# Generated by FakeRAM 2.0
VERSION 5.7 ;
BUSBITCHARS "[]" ;
PROPERTYDEFINITIONS
  MACRO width INTEGER ;
  MACRO depth INTEGER ;
  MACRO banks INTEGER ;
END PROPERTYDEFINITIONS
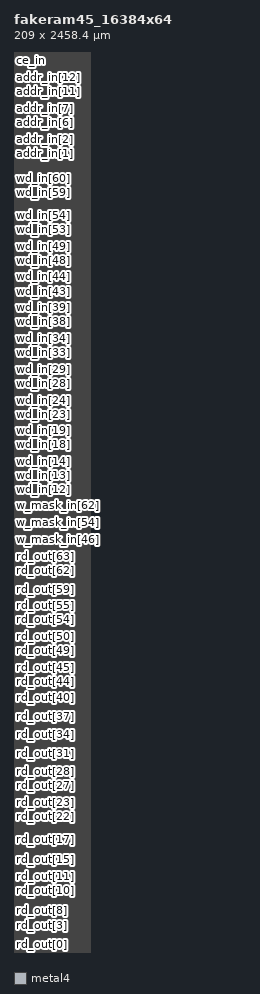
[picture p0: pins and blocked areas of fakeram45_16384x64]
MACRO fakeram45_16384x64
  PROPERTY width 64 ;
  PROPERTY depth 16384 ;
  PROPERTY banks 4 ;
  FOREIGN fakeram45_16384x64 0 0 ;
  SYMMETRY X Y R90 ;
  SIZE 209.000 BY 2458.400 ;
  CLASS BLOCK ;
  PIN rd_out[0]
    DIRECTION OUTPUT ;
    USE SIGNAL ;
    SHAPE ABUTMENT ;
    PORT
      LAYER metal4 ;
      RECT 0.000 0.280 0.140 0.420 ;
    END
  END rd_out[0]
  PIN rd_out[1]
    DIRECTION OUTPUT ;
    USE SIGNAL ;
    SHAPE ABUTMENT ;
    PORT
      LAYER metal4 ;
      RECT 0.000 17.080 0.140 17.220 ;
    END
  END rd_out[1]
  PIN rd_out[2]
    DIRECTION OUTPUT ;
    USE SIGNAL ;
    SHAPE ABUTMENT ;
    PORT
      LAYER metal4 ;
      RECT 0.000 33.880 0.140 34.020 ;
    END
  END rd_out[2]
  PIN rd_out[3]
    DIRECTION OUTPUT ;
    USE SIGNAL ;
    SHAPE ABUTMENT ;
    PORT
      LAYER metal4 ;
      RECT 0.000 50.680 0.140 50.820 ;
    END
  END rd_out[3]
  PIN rd_out[4]
    DIRECTION OUTPUT ;
    USE SIGNAL ;
    SHAPE ABUTMENT ;
    PORT
      LAYER metal4 ;
      RECT 0.000 67.480 0.140 67.620 ;
    END
  END rd_out[4]
  PIN rd_out[5]
    DIRECTION OUTPUT ;
    USE SIGNAL ;
    SHAPE ABUTMENT ;
    PORT
      LAYER metal4 ;
      RECT 0.000 84.280 0.140 84.420 ;
    END
  END rd_out[5]
  PIN rd_out[6]
    DIRECTION OUTPUT ;
    USE SIGNAL ;
    SHAPE ABUTMENT ;
    PORT
      LAYER metal4 ;
      RECT 0.000 101.080 0.140 101.220 ;
    END
  END rd_out[6]
  PIN rd_out[7]
    DIRECTION OUTPUT ;
    USE SIGNAL ;
    SHAPE ABUTMENT ;
    PORT
      LAYER metal4 ;
      RECT 0.000 117.880 0.140 118.020 ;
    END
  END rd_out[7]
  PIN rd_out[8]
    DIRECTION OUTPUT ;
    USE SIGNAL ;
    SHAPE ABUTMENT ;
    PORT
      LAYER metal4 ;
      RECT 0.000 134.680 0.140 134.820 ;
    END
  END rd_out[8]
  PIN rd_out[9]
    DIRECTION OUTPUT ;
    USE SIGNAL ;
    SHAPE ABUTMENT ;
    PORT
      LAYER metal4 ;
      RECT 0.000 151.480 0.140 151.620 ;
    END
  END rd_out[9]
  PIN rd_out[10]
    DIRECTION OUTPUT ;
    USE SIGNAL ;
    SHAPE ABUTMENT ;
    PORT
      LAYER metal4 ;
      RECT 0.000 168.280 0.140 168.420 ;
    END
  END rd_out[10]
  PIN rd_out[11]
    DIRECTION OUTPUT ;
    USE SIGNAL ;
    SHAPE ABUTMENT ;
    PORT
      LAYER metal4 ;
      RECT 0.000 185.080 0.140 185.220 ;
    END
  END rd_out[11]
  PIN rd_out[12]
    DIRECTION OUTPUT ;
    USE SIGNAL ;
    SHAPE ABUTMENT ;
    PORT
      LAYER metal4 ;
      RECT 0.000 201.880 0.140 202.020 ;
    END
  END rd_out[12]
  PIN rd_out[13]
    DIRECTION OUTPUT ;
    USE SIGNAL ;
    SHAPE ABUTMENT ;
    PORT
      LAYER metal4 ;
      RECT 0.000 218.680 0.140 218.820 ;
    END
  END rd_out[13]
  PIN rd_out[14]
    DIRECTION OUTPUT ;
    USE SIGNAL ;
    SHAPE ABUTMENT ;
    PORT
      LAYER metal4 ;
      RECT 0.000 235.480 0.140 235.620 ;
    END
  END rd_out[14]
  PIN rd_out[15]
    DIRECTION OUTPUT ;
    USE SIGNAL ;
    SHAPE ABUTMENT ;
    PORT
      LAYER metal4 ;
      RECT 0.000 252.280 0.140 252.420 ;
    END
  END rd_out[15]
  PIN rd_out[16]
    DIRECTION OUTPUT ;
    USE SIGNAL ;
    SHAPE ABUTMENT ;
    PORT
      LAYER metal4 ;
      RECT 0.000 269.080 0.140 269.220 ;
    END
  END rd_out[16]
  PIN rd_out[17]
    DIRECTION OUTPUT ;
    USE SIGNAL ;
    SHAPE ABUTMENT ;
    PORT
      LAYER metal4 ;
      RECT 0.000 285.880 0.140 286.020 ;
    END
  END rd_out[17]
  PIN rd_out[18]
    DIRECTION OUTPUT ;
    USE SIGNAL ;
    SHAPE ABUTMENT ;
    PORT
      LAYER metal4 ;
      RECT 0.000 302.680 0.140 302.820 ;
    END
  END rd_out[18]
  PIN rd_out[19]
    DIRECTION OUTPUT ;
    USE SIGNAL ;
    SHAPE ABUTMENT ;
    PORT
      LAYER metal4 ;
      RECT 0.000 319.480 0.140 319.620 ;
    END
  END rd_out[19]
  PIN rd_out[20]
    DIRECTION OUTPUT ;
    USE SIGNAL ;
    SHAPE ABUTMENT ;
    PORT
      LAYER metal4 ;
      RECT 0.000 336.280 0.140 336.420 ;
    END
  END rd_out[20]
  PIN rd_out[21]
    DIRECTION OUTPUT ;
    USE SIGNAL ;
    SHAPE ABUTMENT ;
    PORT
      LAYER metal4 ;
      RECT 0.000 353.080 0.140 353.220 ;
    END
  END rd_out[21]
  PIN rd_out[22]
    DIRECTION OUTPUT ;
    USE SIGNAL ;
    SHAPE ABUTMENT ;
    PORT
      LAYER metal4 ;
      RECT 0.000 369.880 0.140 370.020 ;
    END
  END rd_out[22]
  PIN rd_out[23]
    DIRECTION OUTPUT ;
    USE SIGNAL ;
    SHAPE ABUTMENT ;
    PORT
      LAYER metal4 ;
      RECT 0.000 386.680 0.140 386.820 ;
    END
  END rd_out[23]
  PIN rd_out[24]
    DIRECTION OUTPUT ;
    USE SIGNAL ;
    SHAPE ABUTMENT ;
    PORT
      LAYER metal4 ;
      RECT 0.000 403.480 0.140 403.620 ;
    END
  END rd_out[24]
  PIN rd_out[25]
    DIRECTION OUTPUT ;
    USE SIGNAL ;
    SHAPE ABUTMENT ;
    PORT
      LAYER metal4 ;
      RECT 0.000 420.280 0.140 420.420 ;
    END
  END rd_out[25]
  PIN rd_out[26]
    DIRECTION OUTPUT ;
    USE SIGNAL ;
    SHAPE ABUTMENT ;
    PORT
      LAYER metal4 ;
      RECT 0.000 437.080 0.140 437.220 ;
    END
  END rd_out[26]
  PIN rd_out[27]
    DIRECTION OUTPUT ;
    USE SIGNAL ;
    SHAPE ABUTMENT ;
    PORT
      LAYER metal4 ;
      RECT 0.000 453.880 0.140 454.020 ;
    END
  END rd_out[27]
  PIN rd_out[28]
    DIRECTION OUTPUT ;
    USE SIGNAL ;
    SHAPE ABUTMENT ;
    PORT
      LAYER metal4 ;
      RECT 0.000 470.680 0.140 470.820 ;
    END
  END rd_out[28]
  PIN rd_out[29]
    DIRECTION OUTPUT ;
    USE SIGNAL ;
    SHAPE ABUTMENT ;
    PORT
      LAYER metal4 ;
      RECT 0.000 487.480 0.140 487.620 ;
    END
  END rd_out[29]
  PIN rd_out[30]
    DIRECTION OUTPUT ;
    USE SIGNAL ;
    SHAPE ABUTMENT ;
    PORT
      LAYER metal4 ;
      RECT 0.000 504.280 0.140 504.420 ;
    END
  END rd_out[30]
  PIN rd_out[31]
    DIRECTION OUTPUT ;
    USE SIGNAL ;
    SHAPE ABUTMENT ;
    PORT
      LAYER metal4 ;
      RECT 0.000 521.080 0.140 521.220 ;
    END
  END rd_out[31]
  PIN rd_out[32]
    DIRECTION OUTPUT ;
    USE SIGNAL ;
    SHAPE ABUTMENT ;
    PORT
      LAYER metal4 ;
      RECT 0.000 537.880 0.140 538.020 ;
    END
  END rd_out[32]
  PIN rd_out[33]
    DIRECTION OUTPUT ;
    USE SIGNAL ;
    SHAPE ABUTMENT ;
    PORT
      LAYER metal4 ;
      RECT 0.000 554.680 0.140 554.820 ;
    END
  END rd_out[33]
  PIN rd_out[34]
    DIRECTION OUTPUT ;
    USE SIGNAL ;
    SHAPE ABUTMENT ;
    PORT
      LAYER metal4 ;
      RECT 0.000 571.480 0.140 571.620 ;
    END
  END rd_out[34]
  PIN rd_out[35]
    DIRECTION OUTPUT ;
    USE SIGNAL ;
    SHAPE ABUTMENT ;
    PORT
      LAYER metal4 ;
      RECT 0.000 588.280 0.140 588.420 ;
    END
  END rd_out[35]
  PIN rd_out[36]
    DIRECTION OUTPUT ;
    USE SIGNAL ;
    SHAPE ABUTMENT ;
    PORT
      LAYER metal4 ;
      RECT 0.000 605.080 0.140 605.220 ;
    END
  END rd_out[36]
  PIN rd_out[37]
    DIRECTION OUTPUT ;
    USE SIGNAL ;
    SHAPE ABUTMENT ;
    PORT
      LAYER metal4 ;
      RECT 0.000 621.880 0.140 622.020 ;
    END
  END rd_out[37]
  PIN rd_out[38]
    DIRECTION OUTPUT ;
    USE SIGNAL ;
    SHAPE ABUTMENT ;
    PORT
      LAYER metal4 ;
      RECT 0.000 638.680 0.140 638.820 ;
    END
  END rd_out[38]
  PIN rd_out[39]
    DIRECTION OUTPUT ;
    USE SIGNAL ;
    SHAPE ABUTMENT ;
    PORT
      LAYER metal4 ;
      RECT 0.000 655.480 0.140 655.620 ;
    END
  END rd_out[39]
  PIN rd_out[40]
    DIRECTION OUTPUT ;
    USE SIGNAL ;
    SHAPE ABUTMENT ;
    PORT
      LAYER metal4 ;
      RECT 0.000 672.280 0.140 672.420 ;
    END
  END rd_out[40]
  PIN rd_out[41]
    DIRECTION OUTPUT ;
    USE SIGNAL ;
    SHAPE ABUTMENT ;
    PORT
      LAYER metal4 ;
      RECT 0.000 689.080 0.140 689.220 ;
    END
  END rd_out[41]
  PIN rd_out[42]
    DIRECTION OUTPUT ;
    USE SIGNAL ;
    SHAPE ABUTMENT ;
    PORT
      LAYER metal4 ;
      RECT 0.000 705.880 0.140 706.020 ;
    END
  END rd_out[42]
  PIN rd_out[43]
    DIRECTION OUTPUT ;
    USE SIGNAL ;
    SHAPE ABUTMENT ;
    PORT
      LAYER metal4 ;
      RECT 0.000 722.680 0.140 722.820 ;
    END
  END rd_out[43]
  PIN rd_out[44]
    DIRECTION OUTPUT ;
    USE SIGNAL ;
    SHAPE ABUTMENT ;
    PORT
      LAYER metal4 ;
      RECT 0.000 739.480 0.140 739.620 ;
    END
  END rd_out[44]
  PIN rd_out[45]
    DIRECTION OUTPUT ;
    USE SIGNAL ;
    SHAPE ABUTMENT ;
    PORT
      LAYER metal4 ;
      RECT 0.000 756.280 0.140 756.420 ;
    END
  END rd_out[45]
  PIN rd_out[46]
    DIRECTION OUTPUT ;
    USE SIGNAL ;
    SHAPE ABUTMENT ;
    PORT
      LAYER metal4 ;
      RECT 0.000 773.080 0.140 773.220 ;
    END
  END rd_out[46]
  PIN rd_out[47]
    DIRECTION OUTPUT ;
    USE SIGNAL ;
    SHAPE ABUTMENT ;
    PORT
      LAYER metal4 ;
      RECT 0.000 789.880 0.140 790.020 ;
    END
  END rd_out[47]
  PIN rd_out[48]
    DIRECTION OUTPUT ;
    USE SIGNAL ;
    SHAPE ABUTMENT ;
    PORT
      LAYER metal4 ;
      RECT 0.000 806.680 0.140 806.820 ;
    END
  END rd_out[48]
  PIN rd_out[49]
    DIRECTION OUTPUT ;
    USE SIGNAL ;
    SHAPE ABUTMENT ;
    PORT
      LAYER metal4 ;
      RECT 0.000 823.480 0.140 823.620 ;
    END
  END rd_out[49]
  PIN rd_out[50]
    DIRECTION OUTPUT ;
    USE SIGNAL ;
    SHAPE ABUTMENT ;
    PORT
      LAYER metal4 ;
      RECT 0.000 840.280 0.140 840.420 ;
    END
  END rd_out[50]
  PIN rd_out[51]
    DIRECTION OUTPUT ;
    USE SIGNAL ;
    SHAPE ABUTMENT ;
    PORT
      LAYER metal4 ;
      RECT 0.000 857.080 0.140 857.220 ;
    END
  END rd_out[51]
  PIN rd_out[52]
    DIRECTION OUTPUT ;
    USE SIGNAL ;
    SHAPE ABUTMENT ;
    PORT
      LAYER metal4 ;
      RECT 0.000 873.880 0.140 874.020 ;
    END
  END rd_out[52]
  PIN rd_out[53]
    DIRECTION OUTPUT ;
    USE SIGNAL ;
    SHAPE ABUTMENT ;
    PORT
      LAYER metal4 ;
      RECT 0.000 890.680 0.140 890.820 ;
    END
  END rd_out[53]
  PIN rd_out[54]
    DIRECTION OUTPUT ;
    USE SIGNAL ;
    SHAPE ABUTMENT ;
    PORT
      LAYER metal4 ;
      RECT 0.000 907.480 0.140 907.620 ;
    END
  END rd_out[54]
  PIN rd_out[55]
    DIRECTION OUTPUT ;
    USE SIGNAL ;
    SHAPE ABUTMENT ;
    PORT
      LAYER metal4 ;
      RECT 0.000 924.280 0.140 924.420 ;
    END
  END rd_out[55]
  PIN rd_out[56]
    DIRECTION OUTPUT ;
    USE SIGNAL ;
    SHAPE ABUTMENT ;
    PORT
      LAYER metal4 ;
      RECT 0.000 941.080 0.140 941.220 ;
    END
  END rd_out[56]
  PIN rd_out[57]
    DIRECTION OUTPUT ;
    USE SIGNAL ;
    SHAPE ABUTMENT ;
    PORT
      LAYER metal4 ;
      RECT 0.000 957.880 0.140 958.020 ;
    END
  END rd_out[57]
  PIN rd_out[58]
    DIRECTION OUTPUT ;
    USE SIGNAL ;
    SHAPE ABUTMENT ;
    PORT
      LAYER metal4 ;
      RECT 0.000 974.680 0.140 974.820 ;
    END
  END rd_out[58]
  PIN rd_out[59]
    DIRECTION OUTPUT ;
    USE SIGNAL ;
    SHAPE ABUTMENT ;
    PORT
      LAYER metal4 ;
      RECT 0.000 991.480 0.140 991.620 ;
    END
  END rd_out[59]
  PIN rd_out[60]
    DIRECTION OUTPUT ;
    USE SIGNAL ;
    SHAPE ABUTMENT ;
    PORT
      LAYER metal4 ;
      RECT 0.000 1008.280 0.140 1008.420 ;
    END
  END rd_out[60]
  PIN rd_out[61]
    DIRECTION OUTPUT ;
    USE SIGNAL ;
    SHAPE ABUTMENT ;
    PORT
      LAYER metal4 ;
      RECT 0.000 1025.080 0.140 1025.220 ;
    END
  END rd_out[61]
  PIN rd_out[62]
    DIRECTION OUTPUT ;
    USE SIGNAL ;
    SHAPE ABUTMENT ;
    PORT
      LAYER metal4 ;
      RECT 0.000 1041.880 0.140 1042.020 ;
    END
  END rd_out[62]
  PIN rd_out[63]
    DIRECTION OUTPUT ;
    USE SIGNAL ;
    SHAPE ABUTMENT ;
    PORT
      LAYER metal4 ;
      RECT 0.000 1058.680 0.140 1058.820 ;
    END
  END rd_out[63]
  PIN wd_in[0]
    DIRECTION INPUT ;
    USE SIGNAL ;
    SHAPE ABUTMENT ;
    PORT
      LAYER metal4 ;
      RECT 0.000 1082.760 0.140 1082.900 ;
    END
  END wd_in[0]
  PIN wd_in[1]
    DIRECTION INPUT ;
    USE SIGNAL ;
    SHAPE ABUTMENT ;
    PORT
      LAYER metal4 ;
      RECT 0.000 1099.560 0.140 1099.700 ;
    END
  END wd_in[1]
  PIN wd_in[2]
    DIRECTION INPUT ;
    USE SIGNAL ;
    SHAPE ABUTMENT ;
    PORT
      LAYER metal4 ;
      RECT 0.000 1116.360 0.140 1116.500 ;
    END
  END wd_in[2]
  PIN wd_in[3]
    DIRECTION INPUT ;
    USE SIGNAL ;
    SHAPE ABUTMENT ;
    PORT
      LAYER metal4 ;
      RECT 0.000 1133.160 0.140 1133.300 ;
    END
  END wd_in[3]
  PIN wd_in[4]
    DIRECTION INPUT ;
    USE SIGNAL ;
    SHAPE ABUTMENT ;
    PORT
      LAYER metal4 ;
      RECT 0.000 1149.960 0.140 1150.100 ;
    END
  END wd_in[4]
  PIN wd_in[5]
    DIRECTION INPUT ;
    USE SIGNAL ;
    SHAPE ABUTMENT ;
    PORT
      LAYER metal4 ;
      RECT 0.000 1166.760 0.140 1166.900 ;
    END
  END wd_in[5]
  PIN wd_in[6]
    DIRECTION INPUT ;
    USE SIGNAL ;
    SHAPE ABUTMENT ;
    PORT
      LAYER metal4 ;
      RECT 0.000 1183.560 0.140 1183.700 ;
    END
  END wd_in[6]
  PIN wd_in[7]
    DIRECTION INPUT ;
    USE SIGNAL ;
    SHAPE ABUTMENT ;
    PORT
      LAYER metal4 ;
      RECT 0.000 1200.360 0.140 1200.500 ;
    END
  END wd_in[7]
  PIN wd_in[8]
    DIRECTION INPUT ;
    USE SIGNAL ;
    SHAPE ABUTMENT ;
    PORT
      LAYER metal4 ;
      RECT 0.000 1217.160 0.140 1217.300 ;
    END
  END wd_in[8]
  PIN wd_in[9]
    DIRECTION INPUT ;
    USE SIGNAL ;
    SHAPE ABUTMENT ;
    PORT
      LAYER metal4 ;
      RECT 0.000 1233.960 0.140 1234.100 ;
    END
  END wd_in[9]
  PIN wd_in[10]
    DIRECTION INPUT ;
    USE SIGNAL ;
    SHAPE ABUTMENT ;
    PORT
      LAYER metal4 ;
      RECT 0.000 1250.760 0.140 1250.900 ;
    END
  END wd_in[10]
  PIN wd_in[11]
    DIRECTION INPUT ;
    USE SIGNAL ;
    SHAPE ABUTMENT ;
    PORT
      LAYER metal4 ;
      RECT 0.000 1267.560 0.140 1267.700 ;
    END
  END wd_in[11]
  PIN wd_in[12]
    DIRECTION INPUT ;
    USE SIGNAL ;
    SHAPE ABUTMENT ;
    PORT
      LAYER metal4 ;
      RECT 0.000 1284.360 0.140 1284.500 ;
    END
  END wd_in[12]
  PIN wd_in[13]
    DIRECTION INPUT ;
    USE SIGNAL ;
    SHAPE ABUTMENT ;
    PORT
      LAYER metal4 ;
      RECT 0.000 1301.160 0.140 1301.300 ;
    END
  END wd_in[13]
  PIN wd_in[14]
    DIRECTION INPUT ;
    USE SIGNAL ;
    SHAPE ABUTMENT ;
    PORT
      LAYER metal4 ;
      RECT 0.000 1317.960 0.140 1318.100 ;
    END
  END wd_in[14]
  PIN wd_in[15]
    DIRECTION INPUT ;
    USE SIGNAL ;
    SHAPE ABUTMENT ;
    PORT
      LAYER metal4 ;
      RECT 0.000 1334.760 0.140 1334.900 ;
    END
  END wd_in[15]
  PIN wd_in[16]
    DIRECTION INPUT ;
    USE SIGNAL ;
    SHAPE ABUTMENT ;
    PORT
      LAYER metal4 ;
      RECT 0.000 1351.560 0.140 1351.700 ;
    END
  END wd_in[16]
  PIN wd_in[17]
    DIRECTION INPUT ;
    USE SIGNAL ;
    SHAPE ABUTMENT ;
    PORT
      LAYER metal4 ;
      RECT 0.000 1368.360 0.140 1368.500 ;
    END
  END wd_in[17]
  PIN wd_in[18]
    DIRECTION INPUT ;
    USE SIGNAL ;
    SHAPE ABUTMENT ;
    PORT
      LAYER metal4 ;
      RECT 0.000 1385.160 0.140 1385.300 ;
    END
  END wd_in[18]
  PIN wd_in[19]
    DIRECTION INPUT ;
    USE SIGNAL ;
    SHAPE ABUTMENT ;
    PORT
      LAYER metal4 ;
      RECT 0.000 1401.960 0.140 1402.100 ;
    END
  END wd_in[19]
  PIN wd_in[20]
    DIRECTION INPUT ;
    USE SIGNAL ;
    SHAPE ABUTMENT ;
    PORT
      LAYER metal4 ;
      RECT 0.000 1418.760 0.140 1418.900 ;
    END
  END wd_in[20]
  PIN wd_in[21]
    DIRECTION INPUT ;
    USE SIGNAL ;
    SHAPE ABUTMENT ;
    PORT
      LAYER metal4 ;
      RECT 0.000 1435.560 0.140 1435.700 ;
    END
  END wd_in[21]
  PIN wd_in[22]
    DIRECTION INPUT ;
    USE SIGNAL ;
    SHAPE ABUTMENT ;
    PORT
      LAYER metal4 ;
      RECT 0.000 1452.360 0.140 1452.500 ;
    END
  END wd_in[22]
  PIN wd_in[23]
    DIRECTION INPUT ;
    USE SIGNAL ;
    SHAPE ABUTMENT ;
    PORT
      LAYER metal4 ;
      RECT 0.000 1469.160 0.140 1469.300 ;
    END
  END wd_in[23]
  PIN wd_in[24]
    DIRECTION INPUT ;
    USE SIGNAL ;
    SHAPE ABUTMENT ;
    PORT
      LAYER metal4 ;
      RECT 0.000 1485.960 0.140 1486.100 ;
    END
  END wd_in[24]
  PIN wd_in[25]
    DIRECTION INPUT ;
    USE SIGNAL ;
    SHAPE ABUTMENT ;
    PORT
      LAYER metal4 ;
      RECT 0.000 1502.760 0.140 1502.900 ;
    END
  END wd_in[25]
  PIN wd_in[26]
    DIRECTION INPUT ;
    USE SIGNAL ;
    SHAPE ABUTMENT ;
    PORT
      LAYER metal4 ;
      RECT 0.000 1519.560 0.140 1519.700 ;
    END
  END wd_in[26]
  PIN wd_in[27]
    DIRECTION INPUT ;
    USE SIGNAL ;
    SHAPE ABUTMENT ;
    PORT
      LAYER metal4 ;
      RECT 0.000 1536.360 0.140 1536.500 ;
    END
  END wd_in[27]
  PIN wd_in[28]
    DIRECTION INPUT ;
    USE SIGNAL ;
    SHAPE ABUTMENT ;
    PORT
      LAYER metal4 ;
      RECT 0.000 1553.160 0.140 1553.300 ;
    END
  END wd_in[28]
  PIN wd_in[29]
    DIRECTION INPUT ;
    USE SIGNAL ;
    SHAPE ABUTMENT ;
    PORT
      LAYER metal4 ;
      RECT 0.000 1569.960 0.140 1570.100 ;
    END
  END wd_in[29]
  PIN wd_in[30]
    DIRECTION INPUT ;
    USE SIGNAL ;
    SHAPE ABUTMENT ;
    PORT
      LAYER metal4 ;
      RECT 0.000 1586.760 0.140 1586.900 ;
    END
  END wd_in[30]
  PIN wd_in[31]
    DIRECTION INPUT ;
    USE SIGNAL ;
    SHAPE ABUTMENT ;
    PORT
      LAYER metal4 ;
      RECT 0.000 1603.560 0.140 1603.700 ;
    END
  END wd_in[31]
  PIN wd_in[32]
    DIRECTION INPUT ;
    USE SIGNAL ;
    SHAPE ABUTMENT ;
    PORT
      LAYER metal4 ;
      RECT 0.000 1620.360 0.140 1620.500 ;
    END
  END wd_in[32]
  PIN wd_in[33]
    DIRECTION INPUT ;
    USE SIGNAL ;
    SHAPE ABUTMENT ;
    PORT
      LAYER metal4 ;
      RECT 0.000 1637.160 0.140 1637.300 ;
    END
  END wd_in[33]
  PIN wd_in[34]
    DIRECTION INPUT ;
    USE SIGNAL ;
    SHAPE ABUTMENT ;
    PORT
      LAYER metal4 ;
      RECT 0.000 1653.960 0.140 1654.100 ;
    END
  END wd_in[34]
  PIN wd_in[35]
    DIRECTION INPUT ;
    USE SIGNAL ;
    SHAPE ABUTMENT ;
    PORT
      LAYER metal4 ;
      RECT 0.000 1670.760 0.140 1670.900 ;
    END
  END wd_in[35]
  PIN wd_in[36]
    DIRECTION INPUT ;
    USE SIGNAL ;
    SHAPE ABUTMENT ;
    PORT
      LAYER metal4 ;
      RECT 0.000 1687.560 0.140 1687.700 ;
    END
  END wd_in[36]
  PIN wd_in[37]
    DIRECTION INPUT ;
    USE SIGNAL ;
    SHAPE ABUTMENT ;
    PORT
      LAYER metal4 ;
      RECT 0.000 1704.360 0.140 1704.500 ;
    END
  END wd_in[37]
  PIN wd_in[38]
    DIRECTION INPUT ;
    USE SIGNAL ;
    SHAPE ABUTMENT ;
    PORT
      LAYER metal4 ;
      RECT 0.000 1721.160 0.140 1721.300 ;
    END
  END wd_in[38]
  PIN wd_in[39]
    DIRECTION INPUT ;
    USE SIGNAL ;
    SHAPE ABUTMENT ;
    PORT
      LAYER metal4 ;
      RECT 0.000 1737.960 0.140 1738.100 ;
    END
  END wd_in[39]
  PIN wd_in[40]
    DIRECTION INPUT ;
    USE SIGNAL ;
    SHAPE ABUTMENT ;
    PORT
      LAYER metal4 ;
      RECT 0.000 1754.760 0.140 1754.900 ;
    END
  END wd_in[40]
  PIN wd_in[41]
    DIRECTION INPUT ;
    USE SIGNAL ;
    SHAPE ABUTMENT ;
    PORT
      LAYER metal4 ;
      RECT 0.000 1771.560 0.140 1771.700 ;
    END
  END wd_in[41]
  PIN wd_in[42]
    DIRECTION INPUT ;
    USE SIGNAL ;
    SHAPE ABUTMENT ;
    PORT
      LAYER metal4 ;
      RECT 0.000 1788.360 0.140 1788.500 ;
    END
  END wd_in[42]
  PIN wd_in[43]
    DIRECTION INPUT ;
    USE SIGNAL ;
    SHAPE ABUTMENT ;
    PORT
      LAYER metal4 ;
      RECT 0.000 1805.160 0.140 1805.300 ;
    END
  END wd_in[43]
  PIN wd_in[44]
    DIRECTION INPUT ;
    USE SIGNAL ;
    SHAPE ABUTMENT ;
    PORT
      LAYER metal4 ;
      RECT 0.000 1821.960 0.140 1822.100 ;
    END
  END wd_in[44]
  PIN wd_in[45]
    DIRECTION INPUT ;
    USE SIGNAL ;
    SHAPE ABUTMENT ;
    PORT
      LAYER metal4 ;
      RECT 0.000 1838.760 0.140 1838.900 ;
    END
  END wd_in[45]
  PIN wd_in[46]
    DIRECTION INPUT ;
    USE SIGNAL ;
    SHAPE ABUTMENT ;
    PORT
      LAYER metal4 ;
      RECT 0.000 1855.560 0.140 1855.700 ;
    END
  END wd_in[46]
  PIN wd_in[47]
    DIRECTION INPUT ;
    USE SIGNAL ;
    SHAPE ABUTMENT ;
    PORT
      LAYER metal4 ;
      RECT 0.000 1872.360 0.140 1872.500 ;
    END
  END wd_in[47]
  PIN wd_in[48]
    DIRECTION INPUT ;
    USE SIGNAL ;
    SHAPE ABUTMENT ;
    PORT
      LAYER metal4 ;
      RECT 0.000 1889.160 0.140 1889.300 ;
    END
  END wd_in[48]
  PIN wd_in[49]
    DIRECTION INPUT ;
    USE SIGNAL ;
    SHAPE ABUTMENT ;
    PORT
      LAYER metal4 ;
      RECT 0.000 1905.960 0.140 1906.100 ;
    END
  END wd_in[49]
  PIN wd_in[50]
    DIRECTION INPUT ;
    USE SIGNAL ;
    SHAPE ABUTMENT ;
    PORT
      LAYER metal4 ;
      RECT 0.000 1922.760 0.140 1922.900 ;
    END
  END wd_in[50]
  PIN wd_in[51]
    DIRECTION INPUT ;
    USE SIGNAL ;
    SHAPE ABUTMENT ;
    PORT
      LAYER metal4 ;
      RECT 0.000 1939.560 0.140 1939.700 ;
    END
  END wd_in[51]
  PIN wd_in[52]
    DIRECTION INPUT ;
    USE SIGNAL ;
    SHAPE ABUTMENT ;
    PORT
      LAYER metal4 ;
      RECT 0.000 1956.360 0.140 1956.500 ;
    END
  END wd_in[52]
  PIN wd_in[53]
    DIRECTION INPUT ;
    USE SIGNAL ;
    SHAPE ABUTMENT ;
    PORT
      LAYER metal4 ;
      RECT 0.000 1973.160 0.140 1973.300 ;
    END
  END wd_in[53]
  PIN wd_in[54]
    DIRECTION INPUT ;
    USE SIGNAL ;
    SHAPE ABUTMENT ;
    PORT
      LAYER metal4 ;
      RECT 0.000 1989.960 0.140 1990.100 ;
    END
  END wd_in[54]
  PIN wd_in[55]
    DIRECTION INPUT ;
    USE SIGNAL ;
    SHAPE ABUTMENT ;
    PORT
      LAYER metal4 ;
      RECT 0.000 2006.760 0.140 2006.900 ;
    END
  END wd_in[55]
  PIN wd_in[56]
    DIRECTION INPUT ;
    USE SIGNAL ;
    SHAPE ABUTMENT ;
    PORT
      LAYER metal4 ;
      RECT 0.000 2023.560 0.140 2023.700 ;
    END
  END wd_in[56]
  PIN wd_in[57]
    DIRECTION INPUT ;
    USE SIGNAL ;
    SHAPE ABUTMENT ;
    PORT
      LAYER metal4 ;
      RECT 0.000 2040.360 0.140 2040.500 ;
    END
  END wd_in[57]
  PIN wd_in[58]
    DIRECTION INPUT ;
    USE SIGNAL ;
    SHAPE ABUTMENT ;
    PORT
      LAYER metal4 ;
      RECT 0.000 2057.160 0.140 2057.300 ;
    END
  END wd_in[58]
  PIN wd_in[59]
    DIRECTION INPUT ;
    USE SIGNAL ;
    SHAPE ABUTMENT ;
    PORT
      LAYER metal4 ;
      RECT 0.000 2073.960 0.140 2074.100 ;
    END
  END wd_in[59]
  PIN wd_in[60]
    DIRECTION INPUT ;
    USE SIGNAL ;
    SHAPE ABUTMENT ;
    PORT
      LAYER metal4 ;
      RECT 0.000 2090.760 0.140 2090.900 ;
    END
  END wd_in[60]
  PIN wd_in[61]
    DIRECTION INPUT ;
    USE SIGNAL ;
    SHAPE ABUTMENT ;
    PORT
      LAYER metal4 ;
      RECT 0.000 2107.560 0.140 2107.700 ;
    END
  END wd_in[61]
  PIN wd_in[62]
    DIRECTION INPUT ;
    USE SIGNAL ;
    SHAPE ABUTMENT ;
    PORT
      LAYER metal4 ;
      RECT 0.000 2124.360 0.140 2124.500 ;
    END
  END wd_in[62]
  PIN wd_in[63]
    DIRECTION INPUT ;
    USE SIGNAL ;
    SHAPE ABUTMENT ;
    PORT
      LAYER metal4 ;
      RECT 0.000 2141.160 0.140 2141.300 ;
    END
  END wd_in[63]
  PIN addr_in[0]
    DIRECTION INPUT ;
    USE SIGNAL ;
    SHAPE ABUTMENT ;
    PORT
      LAYER metal4 ;
      RECT 0.000 2165.240 0.140 2165.380 ;
    END
  END addr_in[0]
  PIN addr_in[1]
    DIRECTION INPUT ;
    USE SIGNAL ;
    SHAPE ABUTMENT ;
    PORT
      LAYER metal4 ;
      RECT 0.000 2182.040 0.140 2182.180 ;
    END
  END addr_in[1]
  PIN addr_in[2]
    DIRECTION INPUT ;
    USE SIGNAL ;
    SHAPE ABUTMENT ;
    PORT
      LAYER metal4 ;
      RECT 0.000 2198.840 0.140 2198.980 ;
    END
  END addr_in[2]
  PIN addr_in[3]
    DIRECTION INPUT ;
    USE SIGNAL ;
    SHAPE ABUTMENT ;
    PORT
      LAYER metal4 ;
      RECT 0.000 2215.640 0.140 2215.780 ;
    END
  END addr_in[3]
  PIN addr_in[4]
    DIRECTION INPUT ;
    USE SIGNAL ;
    SHAPE ABUTMENT ;
    PORT
      LAYER metal4 ;
      RECT 0.000 2232.440 0.140 2232.580 ;
    END
  END addr_in[4]
  PIN addr_in[5]
    DIRECTION INPUT ;
    USE SIGNAL ;
    SHAPE ABUTMENT ;
    PORT
      LAYER metal4 ;
      RECT 0.000 2249.240 0.140 2249.380 ;
    END
  END addr_in[5]
  PIN addr_in[6]
    DIRECTION INPUT ;
    USE SIGNAL ;
    SHAPE ABUTMENT ;
    PORT
      LAYER metal4 ;
      RECT 0.000 2266.040 0.140 2266.180 ;
    END
  END addr_in[6]
  PIN addr_in[7]
    DIRECTION INPUT ;
    USE SIGNAL ;
    SHAPE ABUTMENT ;
    PORT
      LAYER metal4 ;
      RECT 0.000 2282.840 0.140 2282.980 ;
    END
  END addr_in[7]
  PIN addr_in[8]
    DIRECTION INPUT ;
    USE SIGNAL ;
    SHAPE ABUTMENT ;
    PORT
      LAYER metal4 ;
      RECT 0.000 2299.640 0.140 2299.780 ;
    END
  END addr_in[8]
  PIN addr_in[9]
    DIRECTION INPUT ;
    USE SIGNAL ;
    SHAPE ABUTMENT ;
    PORT
      LAYER metal4 ;
      RECT 0.000 2316.440 0.140 2316.580 ;
    END
  END addr_in[9]
  PIN addr_in[10]
    DIRECTION INPUT ;
    USE SIGNAL ;
    SHAPE ABUTMENT ;
    PORT
      LAYER metal4 ;
      RECT 0.000 2333.240 0.140 2333.380 ;
    END
  END addr_in[10]
  PIN addr_in[11]
    DIRECTION INPUT ;
    USE SIGNAL ;
    SHAPE ABUTMENT ;
    PORT
      LAYER metal4 ;
      RECT 0.000 2350.040 0.140 2350.180 ;
    END
  END addr_in[11]
  PIN addr_in[12]
    DIRECTION INPUT ;
    USE SIGNAL ;
    SHAPE ABUTMENT ;
    PORT
      LAYER metal4 ;
      RECT 0.000 2366.840 0.140 2366.980 ;
    END
  END addr_in[12]
  PIN addr_in[13]
    DIRECTION INPUT ;
    USE SIGNAL ;
    SHAPE ABUTMENT ;
    PORT
      LAYER metal4 ;
      RECT 0.000 2383.640 0.140 2383.780 ;
    END
  END addr_in[13]
  PIN we_in
    DIRECTION INPUT ;
    USE SIGNAL ;
    SHAPE ABUTMENT ;
    PORT
      LAYER metal4 ;
      RECT 0.000 2407.720 0.140 2407.860 ;
    END
  END we_in
  PIN ce_in
    DIRECTION INPUT ;
    USE SIGNAL ;
    SHAPE ABUTMENT ;
    PORT
      LAYER metal4 ;
      RECT 0.000 2424.520 0.140 2424.660 ;
    END
  END ce_in
  PIN clk
    DIRECTION INPUT ;
    USE SIGNAL ;
    SHAPE ABUTMENT ;
    PORT
      LAYER metal4 ;
      RECT 0.000 2441.320 0.140 2441.460 ;
    END
  END clk
  PIN w_mask_in[0]
    DIRECTION OUTPUT ;
    USE SIGNAL ;
    SHAPE ABUTMENT ;
    PORT
      LAYER metal4 ;
      RECT 0.000 834.400 0.140 834.540 ;
    END
  END w_mask_in[0]
  PIN w_mask_in[1]
    DIRECTION OUTPUT ;
    USE SIGNAL ;
    SHAPE ABUTMENT ;
    PORT
      LAYER metal4 ;
      RECT 0.000 840.280 0.140 840.420 ;
    END
  END w_mask_in[1]
  PIN w_mask_in[2]
    DIRECTION OUTPUT ;
    USE SIGNAL ;
    SHAPE ABUTMENT ;
    PORT
      LAYER metal4 ;
      RECT 0.000 846.160 0.140 846.300 ;
    END
  END w_mask_in[2]
  PIN w_mask_in[3]
    DIRECTION OUTPUT ;
    USE SIGNAL ;
    SHAPE ABUTMENT ;
    PORT
      LAYER metal4 ;
      RECT 0.000 852.040 0.140 852.180 ;
    END
  END w_mask_in[3]
  PIN w_mask_in[4]
    DIRECTION OUTPUT ;
    USE SIGNAL ;
    SHAPE ABUTMENT ;
    PORT
      LAYER metal4 ;
      RECT 0.000 857.920 0.140 858.060 ;
    END
  END w_mask_in[4]
  PIN w_mask_in[5]
    DIRECTION OUTPUT ;
    USE SIGNAL ;
    SHAPE ABUTMENT ;
    PORT
      LAYER metal4 ;
      RECT 0.000 863.800 0.140 863.940 ;
    END
  END w_mask_in[5]
  PIN w_mask_in[6]
    DIRECTION OUTPUT ;
    USE SIGNAL ;
    SHAPE ABUTMENT ;
    PORT
      LAYER metal4 ;
      RECT 0.000 869.680 0.140 869.820 ;
    END
  END w_mask_in[6]
  PIN w_mask_in[7]
    DIRECTION OUTPUT ;
    USE SIGNAL ;
    SHAPE ABUTMENT ;
    PORT
      LAYER metal4 ;
      RECT 0.000 875.560 0.140 875.700 ;
    END
  END w_mask_in[7]
  PIN w_mask_in[8]
    DIRECTION OUTPUT ;
    USE SIGNAL ;
    SHAPE ABUTMENT ;
    PORT
      LAYER metal4 ;
      RECT 0.000 881.440 0.140 881.580 ;
    END
  END w_mask_in[8]
  PIN w_mask_in[9]
    DIRECTION OUTPUT ;
    USE SIGNAL ;
    SHAPE ABUTMENT ;
    PORT
      LAYER metal4 ;
      RECT 0.000 887.320 0.140 887.460 ;
    END
  END w_mask_in[9]
  PIN w_mask_in[10]
    DIRECTION OUTPUT ;
    USE SIGNAL ;
    SHAPE ABUTMENT ;
    PORT
      LAYER metal4 ;
      RECT 0.000 893.200 0.140 893.340 ;
    END
  END w_mask_in[10]
  PIN w_mask_in[11]
    DIRECTION OUTPUT ;
    USE SIGNAL ;
    SHAPE ABUTMENT ;
    PORT
      LAYER metal4 ;
      RECT 0.000 899.080 0.140 899.220 ;
    END
  END w_mask_in[11]
  PIN w_mask_in[12]
    DIRECTION OUTPUT ;
    USE SIGNAL ;
    SHAPE ABUTMENT ;
    PORT
      LAYER metal4 ;
      RECT 0.000 904.960 0.140 905.100 ;
    END
  END w_mask_in[12]
  PIN w_mask_in[13]
    DIRECTION OUTPUT ;
    USE SIGNAL ;
    SHAPE ABUTMENT ;
    PORT
      LAYER metal4 ;
      RECT 0.000 910.840 0.140 910.980 ;
    END
  END w_mask_in[13]
  PIN w_mask_in[14]
    DIRECTION OUTPUT ;
    USE SIGNAL ;
    SHAPE ABUTMENT ;
    PORT
      LAYER metal4 ;
      RECT 0.000 916.720 0.140 916.860 ;
    END
  END w_mask_in[14]
  PIN w_mask_in[15]
    DIRECTION OUTPUT ;
    USE SIGNAL ;
    SHAPE ABUTMENT ;
    PORT
      LAYER metal4 ;
      RECT 0.000 922.600 0.140 922.740 ;
    END
  END w_mask_in[15]
  PIN w_mask_in[16]
    DIRECTION OUTPUT ;
    USE SIGNAL ;
    SHAPE ABUTMENT ;
    PORT
      LAYER metal4 ;
      RECT 0.000 928.480 0.140 928.620 ;
    END
  END w_mask_in[16]
  PIN w_mask_in[17]
    DIRECTION OUTPUT ;
    USE SIGNAL ;
    SHAPE ABUTMENT ;
    PORT
      LAYER metal4 ;
      RECT 0.000 934.360 0.140 934.500 ;
    END
  END w_mask_in[17]
  PIN w_mask_in[18]
    DIRECTION OUTPUT ;
    USE SIGNAL ;
    SHAPE ABUTMENT ;
    PORT
      LAYER metal4 ;
      RECT 0.000 940.240 0.140 940.380 ;
    END
  END w_mask_in[18]
  PIN w_mask_in[19]
    DIRECTION OUTPUT ;
    USE SIGNAL ;
    SHAPE ABUTMENT ;
    PORT
      LAYER metal4 ;
      RECT 0.000 946.120 0.140 946.260 ;
    END
  END w_mask_in[19]
  PIN w_mask_in[20]
    DIRECTION OUTPUT ;
    USE SIGNAL ;
    SHAPE ABUTMENT ;
    PORT
      LAYER metal4 ;
      RECT 0.000 952.000 0.140 952.140 ;
    END
  END w_mask_in[20]
  PIN w_mask_in[21]
    DIRECTION OUTPUT ;
    USE SIGNAL ;
    SHAPE ABUTMENT ;
    PORT
      LAYER metal4 ;
      RECT 0.000 957.880 0.140 958.020 ;
    END
  END w_mask_in[21]
  PIN w_mask_in[22]
    DIRECTION OUTPUT ;
    USE SIGNAL ;
    SHAPE ABUTMENT ;
    PORT
      LAYER metal4 ;
      RECT 0.000 963.760 0.140 963.900 ;
    END
  END w_mask_in[22]
  PIN w_mask_in[23]
    DIRECTION OUTPUT ;
    USE SIGNAL ;
    SHAPE ABUTMENT ;
    PORT
      LAYER metal4 ;
      RECT 0.000 969.640 0.140 969.780 ;
    END
  END w_mask_in[23]
  PIN w_mask_in[24]
    DIRECTION OUTPUT ;
    USE SIGNAL ;
    SHAPE ABUTMENT ;
    PORT
      LAYER metal4 ;
      RECT 0.000 975.520 0.140 975.660 ;
    END
  END w_mask_in[24]
  PIN w_mask_in[25]
    DIRECTION OUTPUT ;
    USE SIGNAL ;
    SHAPE ABUTMENT ;
    PORT
      LAYER metal4 ;
      RECT 0.000 981.400 0.140 981.540 ;
    END
  END w_mask_in[25]
  PIN w_mask_in[26]
    DIRECTION OUTPUT ;
    USE SIGNAL ;
    SHAPE ABUTMENT ;
    PORT
      LAYER metal4 ;
      RECT 0.000 987.280 0.140 987.420 ;
    END
  END w_mask_in[26]
  PIN w_mask_in[27]
    DIRECTION OUTPUT ;
    USE SIGNAL ;
    SHAPE ABUTMENT ;
    PORT
      LAYER metal4 ;
      RECT 0.000 993.160 0.140 993.300 ;
    END
  END w_mask_in[27]
  PIN w_mask_in[28]
    DIRECTION OUTPUT ;
    USE SIGNAL ;
    SHAPE ABUTMENT ;
    PORT
      LAYER metal4 ;
      RECT 0.000 999.040 0.140 999.180 ;
    END
  END w_mask_in[28]
  PIN w_mask_in[29]
    DIRECTION OUTPUT ;
    USE SIGNAL ;
    SHAPE ABUTMENT ;
    PORT
      LAYER metal4 ;
      RECT 0.000 1004.920 0.140 1005.060 ;
    END
  END w_mask_in[29]
  PIN w_mask_in[30]
    DIRECTION OUTPUT ;
    USE SIGNAL ;
    SHAPE ABUTMENT ;
    PORT
      LAYER metal4 ;
      RECT 0.000 1010.800 0.140 1010.940 ;
    END
  END w_mask_in[30]
  PIN w_mask_in[31]
    DIRECTION OUTPUT ;
    USE SIGNAL ;
    SHAPE ABUTMENT ;
    PORT
      LAYER metal4 ;
      RECT 0.000 1016.680 0.140 1016.820 ;
    END
  END w_mask_in[31]
  PIN w_mask_in[32]
    DIRECTION OUTPUT ;
    USE SIGNAL ;
    SHAPE ABUTMENT ;
    PORT
      LAYER metal4 ;
      RECT 0.000 1022.560 0.140 1022.700 ;
    END
  END w_mask_in[32]
  PIN w_mask_in[33]
    DIRECTION OUTPUT ;
    USE SIGNAL ;
    SHAPE ABUTMENT ;
    PORT
      LAYER metal4 ;
      RECT 0.000 1028.440 0.140 1028.580 ;
    END
  END w_mask_in[33]
  PIN w_mask_in[34]
    DIRECTION OUTPUT ;
    USE SIGNAL ;
    SHAPE ABUTMENT ;
    PORT
      LAYER metal4 ;
      RECT 0.000 1034.320 0.140 1034.460 ;
    END
  END w_mask_in[34]
  PIN w_mask_in[35]
    DIRECTION OUTPUT ;
    USE SIGNAL ;
    SHAPE ABUTMENT ;
    PORT
      LAYER metal4 ;
      RECT 0.000 1040.200 0.140 1040.340 ;
    END
  END w_mask_in[35]
  PIN w_mask_in[36]
    DIRECTION OUTPUT ;
    USE SIGNAL ;
    SHAPE ABUTMENT ;
    PORT
      LAYER metal4 ;
      RECT 0.000 1046.080 0.140 1046.220 ;
    END
  END w_mask_in[36]
  PIN w_mask_in[37]
    DIRECTION OUTPUT ;
    USE SIGNAL ;
    SHAPE ABUTMENT ;
    PORT
      LAYER metal4 ;
      RECT 0.000 1051.960 0.140 1052.100 ;
    END
  END w_mask_in[37]
  PIN w_mask_in[38]
    DIRECTION OUTPUT ;
    USE SIGNAL ;
    SHAPE ABUTMENT ;
    PORT
      LAYER metal4 ;
      RECT 0.000 1057.840 0.140 1057.980 ;
    END
  END w_mask_in[38]
  PIN w_mask_in[39]
    DIRECTION OUTPUT ;
    USE SIGNAL ;
    SHAPE ABUTMENT ;
    PORT
      LAYER metal4 ;
      RECT 0.000 1063.720 0.140 1063.860 ;
    END
  END w_mask_in[39]
  PIN w_mask_in[40]
    DIRECTION OUTPUT ;
    USE SIGNAL ;
    SHAPE ABUTMENT ;
    PORT
      LAYER metal4 ;
      RECT 0.000 1069.600 0.140 1069.740 ;
    END
  END w_mask_in[40]
  PIN w_mask_in[41]
    DIRECTION OUTPUT ;
    USE SIGNAL ;
    SHAPE ABUTMENT ;
    PORT
      LAYER metal4 ;
      RECT 0.000 1075.480 0.140 1075.620 ;
    END
  END w_mask_in[41]
  PIN w_mask_in[42]
    DIRECTION OUTPUT ;
    USE SIGNAL ;
    SHAPE ABUTMENT ;
    PORT
      LAYER metal4 ;
      RECT 0.000 1081.360 0.140 1081.500 ;
    END
  END w_mask_in[42]
  PIN w_mask_in[43]
    DIRECTION OUTPUT ;
    USE SIGNAL ;
    SHAPE ABUTMENT ;
    PORT
      LAYER metal4 ;
      RECT 0.000 1087.240 0.140 1087.380 ;
    END
  END w_mask_in[43]
  PIN w_mask_in[44]
    DIRECTION OUTPUT ;
    USE SIGNAL ;
    SHAPE ABUTMENT ;
    PORT
      LAYER metal4 ;
      RECT 0.000 1093.120 0.140 1093.260 ;
    END
  END w_mask_in[44]
  PIN w_mask_in[45]
    DIRECTION OUTPUT ;
    USE SIGNAL ;
    SHAPE ABUTMENT ;
    PORT
      LAYER metal4 ;
      RECT 0.000 1099.000 0.140 1099.140 ;
    END
  END w_mask_in[45]
  PIN w_mask_in[46]
    DIRECTION OUTPUT ;
    USE SIGNAL ;
    SHAPE ABUTMENT ;
    PORT
      LAYER metal4 ;
      RECT 0.000 1104.880 0.140 1105.020 ;
    END
  END w_mask_in[46]
  PIN w_mask_in[47]
    DIRECTION OUTPUT ;
    USE SIGNAL ;
    SHAPE ABUTMENT ;
    PORT
      LAYER metal4 ;
      RECT 0.000 1110.760 0.140 1110.900 ;
    END
  END w_mask_in[47]
  PIN w_mask_in[48]
    DIRECTION OUTPUT ;
    USE SIGNAL ;
    SHAPE ABUTMENT ;
    PORT
      LAYER metal4 ;
      RECT 0.000 1116.640 0.140 1116.780 ;
    END
  END w_mask_in[48]
  PIN w_mask_in[49]
    DIRECTION OUTPUT ;
    USE SIGNAL ;
    SHAPE ABUTMENT ;
    PORT
      LAYER metal4 ;
      RECT 0.000 1122.520 0.140 1122.660 ;
    END
  END w_mask_in[49]
  PIN w_mask_in[50]
    DIRECTION OUTPUT ;
    USE SIGNAL ;
    SHAPE ABUTMENT ;
    PORT
      LAYER metal4 ;
      RECT 0.000 1128.400 0.140 1128.540 ;
    END
  END w_mask_in[50]
  PIN w_mask_in[51]
    DIRECTION OUTPUT ;
    USE SIGNAL ;
    SHAPE ABUTMENT ;
    PORT
      LAYER metal4 ;
      RECT 0.000 1134.280 0.140 1134.420 ;
    END
  END w_mask_in[51]
  PIN w_mask_in[52]
    DIRECTION OUTPUT ;
    USE SIGNAL ;
    SHAPE ABUTMENT ;
    PORT
      LAYER metal4 ;
      RECT 0.000 1140.160 0.140 1140.300 ;
    END
  END w_mask_in[52]
  PIN w_mask_in[53]
    DIRECTION OUTPUT ;
    USE SIGNAL ;
    SHAPE ABUTMENT ;
    PORT
      LAYER metal4 ;
      RECT 0.000 1146.040 0.140 1146.180 ;
    END
  END w_mask_in[53]
  PIN w_mask_in[54]
    DIRECTION OUTPUT ;
    USE SIGNAL ;
    SHAPE ABUTMENT ;
    PORT
      LAYER metal4 ;
      RECT 0.000 1151.920 0.140 1152.060 ;
    END
  END w_mask_in[54]
  PIN w_mask_in[55]
    DIRECTION OUTPUT ;
    USE SIGNAL ;
    SHAPE ABUTMENT ;
    PORT
      LAYER metal4 ;
      RECT 0.000 1157.800 0.140 1157.940 ;
    END
  END w_mask_in[55]
  PIN w_mask_in[56]
    DIRECTION OUTPUT ;
    USE SIGNAL ;
    SHAPE ABUTMENT ;
    PORT
      LAYER metal4 ;
      RECT 0.000 1163.680 0.140 1163.820 ;
    END
  END w_mask_in[56]
  PIN w_mask_in[57]
    DIRECTION OUTPUT ;
    USE SIGNAL ;
    SHAPE ABUTMENT ;
    PORT
      LAYER metal4 ;
      RECT 0.000 1169.560 0.140 1169.700 ;
    END
  END w_mask_in[57]
  PIN w_mask_in[58]
    DIRECTION OUTPUT ;
    USE SIGNAL ;
    SHAPE ABUTMENT ;
    PORT
      LAYER metal4 ;
      RECT 0.000 1175.440 0.140 1175.580 ;
    END
  END w_mask_in[58]
  PIN w_mask_in[59]
    DIRECTION OUTPUT ;
    USE SIGNAL ;
    SHAPE ABUTMENT ;
    PORT
      LAYER metal4 ;
      RECT 0.000 1181.320 0.140 1181.460 ;
    END
  END w_mask_in[59]
  PIN w_mask_in[60]
    DIRECTION OUTPUT ;
    USE SIGNAL ;
    SHAPE ABUTMENT ;
    PORT
      LAYER metal4 ;
      RECT 0.000 1187.200 0.140 1187.340 ;
    END
  END w_mask_in[60]
  PIN w_mask_in[61]
    DIRECTION OUTPUT ;
    USE SIGNAL ;
    SHAPE ABUTMENT ;
    PORT
      LAYER metal4 ;
      RECT 0.000 1193.080 0.140 1193.220 ;
    END
  END w_mask_in[61]
  PIN w_mask_in[62]
    DIRECTION OUTPUT ;
    USE SIGNAL ;
    SHAPE ABUTMENT ;
    PORT
      LAYER metal4 ;
      RECT 0.000 1198.960 0.140 1199.100 ;
    END
  END w_mask_in[62]
  PIN w_mask_in[63]
    DIRECTION OUTPUT ;
    USE SIGNAL ;
    SHAPE ABUTMENT ;
    PORT
      LAYER metal4 ;
      RECT 0.000 1204.840 0.140 1204.980 ;
    END
  END w_mask_in[63]
  PIN VSS
    DIRECTION INOUT ;
    USE GROUND ;
    PORT
      LAYER metal4 ;
      RECT 0.280 0.000 208.720 0.560 ;
      RECT 0.280 4.480 208.720 5.040 ;
      RECT 0.280 8.960 208.720 9.520 ;
      RECT 0.280 13.440 208.720 14.000 ;
      RECT 0.280 17.920 208.720 18.480 ;
      RECT 0.280 22.400 208.720 22.960 ;
      RECT 0.280 26.880 208.720 27.440 ;
      RECT 0.280 31.360 208.720 31.920 ;
      RECT 0.280 35.840 208.720 36.400 ;
      RECT 0.280 40.320 208.720 40.880 ;
      RECT 0.280 44.800 208.720 45.360 ;
      RECT 0.280 49.280 208.720 49.840 ;
      RECT 0.280 53.760 208.720 54.320 ;
      RECT 0.280 58.240 208.720 58.800 ;
      RECT 0.280 62.720 208.720 63.280 ;
      RECT 0.280 67.200 208.720 67.760 ;
      RECT 0.280 71.680 208.720 72.240 ;
      RECT 0.280 76.160 208.720 76.720 ;
      RECT 0.280 80.640 208.720 81.200 ;
      RECT 0.280 85.120 208.720 85.680 ;
      RECT 0.280 89.600 208.720 90.160 ;
      RECT 0.280 94.080 208.720 94.640 ;
      RECT 0.280 98.560 208.720 99.120 ;
      RECT 0.280 103.040 208.720 103.600 ;
      RECT 0.280 107.520 208.720 108.080 ;
      RECT 0.280 112.000 208.720 112.560 ;
      RECT 0.280 116.480 208.720 117.040 ;
      RECT 0.280 120.960 208.720 121.520 ;
      RECT 0.280 125.440 208.720 126.000 ;
      RECT 0.280 129.920 208.720 130.480 ;
      RECT 0.280 134.400 208.720 134.960 ;
      RECT 0.280 138.880 208.720 139.440 ;
      RECT 0.280 143.360 208.720 143.920 ;
      RECT 0.280 147.840 208.720 148.400 ;
      RECT 0.280 152.320 208.720 152.880 ;
      RECT 0.280 156.800 208.720 157.360 ;
      RECT 0.280 161.280 208.720 161.840 ;
      RECT 0.280 165.760 208.720 166.320 ;
      RECT 0.280 170.240 208.720 170.800 ;
      RECT 0.280 174.720 208.720 175.280 ;
      RECT 0.280 179.200 208.720 179.760 ;
      RECT 0.280 183.680 208.720 184.240 ;
      RECT 0.280 188.160 208.720 188.720 ;
      RECT 0.280 192.640 208.720 193.200 ;
      RECT 0.280 197.120 208.720 197.680 ;
      RECT 0.280 201.600 208.720 202.160 ;
      RECT 0.280 206.080 208.720 206.640 ;
      RECT 0.280 210.560 208.720 211.120 ;
      RECT 0.280 215.040 208.720 215.600 ;
      RECT 0.280 219.520 208.720 220.080 ;
      RECT 0.280 224.000 208.720 224.560 ;
      RECT 0.280 228.480 208.720 229.040 ;
      RECT 0.280 232.960 208.720 233.520 ;
      RECT 0.280 237.440 208.720 238.000 ;
      RECT 0.280 241.920 208.720 242.480 ;
      RECT 0.280 246.400 208.720 246.960 ;
      RECT 0.280 250.880 208.720 251.440 ;
      RECT 0.280 255.360 208.720 255.920 ;
      RECT 0.280 259.840 208.720 260.400 ;
      RECT 0.280 264.320 208.720 264.880 ;
      RECT 0.280 268.800 208.720 269.360 ;
      RECT 0.280 273.280 208.720 273.840 ;
      RECT 0.280 277.760 208.720 278.320 ;
      RECT 0.280 282.240 208.720 282.800 ;
      RECT 0.280 286.720 208.720 287.280 ;
      RECT 0.280 291.200 208.720 291.760 ;
      RECT 0.280 295.680 208.720 296.240 ;
      RECT 0.280 300.160 208.720 300.720 ;
      RECT 0.280 304.640 208.720 305.200 ;
      RECT 0.280 309.120 208.720 309.680 ;
      RECT 0.280 313.600 208.720 314.160 ;
      RECT 0.280 318.080 208.720 318.640 ;
      RECT 0.280 322.560 208.720 323.120 ;
      RECT 0.280 327.040 208.720 327.600 ;
      RECT 0.280 331.520 208.720 332.080 ;
      RECT 0.280 336.000 208.720 336.560 ;
      RECT 0.280 340.480 208.720 341.040 ;
      RECT 0.280 344.960 208.720 345.520 ;
      RECT 0.280 349.440 208.720 350.000 ;
      RECT 0.280 353.920 208.720 354.480 ;
      RECT 0.280 358.400 208.720 358.960 ;
      RECT 0.280 362.880 208.720 363.440 ;
      RECT 0.280 367.360 208.720 367.920 ;
      RECT 0.280 371.840 208.720 372.400 ;
      RECT 0.280 376.320 208.720 376.880 ;
      RECT 0.280 380.800 208.720 381.360 ;
      RECT 0.280 385.280 208.720 385.840 ;
      RECT 0.280 389.760 208.720 390.320 ;
      RECT 0.280 394.240 208.720 394.800 ;
      RECT 0.280 398.720 208.720 399.280 ;
      RECT 0.280 403.200 208.720 403.760 ;
      RECT 0.280 407.680 208.720 408.240 ;
      RECT 0.280 412.160 208.720 412.720 ;
      RECT 0.280 416.640 208.720 417.200 ;
      RECT 0.280 421.120 208.720 421.680 ;
      RECT 0.280 425.600 208.720 426.160 ;
      RECT 0.280 430.080 208.720 430.640 ;
      RECT 0.280 434.560 208.720 435.120 ;
      RECT 0.280 439.040 208.720 439.600 ;
      RECT 0.280 443.520 208.720 444.080 ;
      RECT 0.280 448.000 208.720 448.560 ;
      RECT 0.280 452.480 208.720 453.040 ;
      RECT 0.280 456.960 208.720 457.520 ;
      RECT 0.280 461.440 208.720 462.000 ;
      RECT 0.280 465.920 208.720 466.480 ;
      RECT 0.280 470.400 208.720 470.960 ;
      RECT 0.280 474.880 208.720 475.440 ;
      RECT 0.280 479.360 208.720 479.920 ;
      RECT 0.280 483.840 208.720 484.400 ;
      RECT 0.280 488.320 208.720 488.880 ;
      RECT 0.280 492.800 208.720 493.360 ;
      RECT 0.280 497.280 208.720 497.840 ;
      RECT 0.280 501.760 208.720 502.320 ;
      RECT 0.280 506.240 208.720 506.800 ;
      RECT 0.280 510.720 208.720 511.280 ;
      RECT 0.280 515.200 208.720 515.760 ;
      RECT 0.280 519.680 208.720 520.240 ;
      RECT 0.280 524.160 208.720 524.720 ;
      RECT 0.280 528.640 208.720 529.200 ;
      RECT 0.280 533.120 208.720 533.680 ;
      RECT 0.280 537.600 208.720 538.160 ;
      RECT 0.280 542.080 208.720 542.640 ;
      RECT 0.280 546.560 208.720 547.120 ;
      RECT 0.280 551.040 208.720 551.600 ;
      RECT 0.280 555.520 208.720 556.080 ;
      RECT 0.280 560.000 208.720 560.560 ;
      RECT 0.280 564.480 208.720 565.040 ;
      RECT 0.280 568.960 208.720 569.520 ;
      RECT 0.280 573.440 208.720 574.000 ;
      RECT 0.280 577.920 208.720 578.480 ;
      RECT 0.280 582.400 208.720 582.960 ;
      RECT 0.280 586.880 208.720 587.440 ;
      RECT 0.280 591.360 208.720 591.920 ;
      RECT 0.280 595.840 208.720 596.400 ;
      RECT 0.280 600.320 208.720 600.880 ;
      RECT 0.280 604.800 208.720 605.360 ;
      RECT 0.280 609.280 208.720 609.840 ;
      RECT 0.280 613.760 208.720 614.320 ;
      RECT 0.280 618.240 208.720 618.800 ;
      RECT 0.280 622.720 208.720 623.280 ;
      RECT 0.280 627.200 208.720 627.760 ;
      RECT 0.280 631.680 208.720 632.240 ;
      RECT 0.280 636.160 208.720 636.720 ;
      RECT 0.280 640.640 208.720 641.200 ;
      RECT 0.280 645.120 208.720 645.680 ;
      RECT 0.280 649.600 208.720 650.160 ;
      RECT 0.280 654.080 208.720 654.640 ;
      RECT 0.280 658.560 208.720 659.120 ;
      RECT 0.280 663.040 208.720 663.600 ;
      RECT 0.280 667.520 208.720 668.080 ;
      RECT 0.280 672.000 208.720 672.560 ;
      RECT 0.280 676.480 208.720 677.040 ;
      RECT 0.280 680.960 208.720 681.520 ;
      RECT 0.280 685.440 208.720 686.000 ;
      RECT 0.280 689.920 208.720 690.480 ;
      RECT 0.280 694.400 208.720 694.960 ;
      RECT 0.280 698.880 208.720 699.440 ;
      RECT 0.280 703.360 208.720 703.920 ;
      RECT 0.280 707.840 208.720 708.400 ;
      RECT 0.280 712.320 208.720 712.880 ;
      RECT 0.280 716.800 208.720 717.360 ;
      RECT 0.280 721.280 208.720 721.840 ;
      RECT 0.280 725.760 208.720 726.320 ;
      RECT 0.280 730.240 208.720 730.800 ;
      RECT 0.280 734.720 208.720 735.280 ;
      RECT 0.280 739.200 208.720 739.760 ;
      RECT 0.280 743.680 208.720 744.240 ;
      RECT 0.280 748.160 208.720 748.720 ;
      RECT 0.280 752.640 208.720 753.200 ;
      RECT 0.280 757.120 208.720 757.680 ;
      RECT 0.280 761.600 208.720 762.160 ;
      RECT 0.280 766.080 208.720 766.640 ;
      RECT 0.280 770.560 208.720 771.120 ;
      RECT 0.280 775.040 208.720 775.600 ;
      RECT 0.280 779.520 208.720 780.080 ;
      RECT 0.280 784.000 208.720 784.560 ;
      RECT 0.280 788.480 208.720 789.040 ;
      RECT 0.280 792.960 208.720 793.520 ;
      RECT 0.280 797.440 208.720 798.000 ;
      RECT 0.280 801.920 208.720 802.480 ;
      RECT 0.280 806.400 208.720 806.960 ;
      RECT 0.280 810.880 208.720 811.440 ;
      RECT 0.280 815.360 208.720 815.920 ;
      RECT 0.280 819.840 208.720 820.400 ;
      RECT 0.280 824.320 208.720 824.880 ;
      RECT 0.280 828.800 208.720 829.360 ;
      RECT 0.280 833.280 208.720 833.840 ;
      RECT 0.280 837.760 208.720 838.320 ;
      RECT 0.280 842.240 208.720 842.800 ;
      RECT 0.280 846.720 208.720 847.280 ;
      RECT 0.280 851.200 208.720 851.760 ;
      RECT 0.280 855.680 208.720 856.240 ;
      RECT 0.280 860.160 208.720 860.720 ;
      RECT 0.280 864.640 208.720 865.200 ;
      RECT 0.280 869.120 208.720 869.680 ;
      RECT 0.280 873.600 208.720 874.160 ;
      RECT 0.280 878.080 208.720 878.640 ;
      RECT 0.280 882.560 208.720 883.120 ;
      RECT 0.280 887.040 208.720 887.600 ;
      RECT 0.280 891.520 208.720 892.080 ;
      RECT 0.280 896.000 208.720 896.560 ;
      RECT 0.280 900.480 208.720 901.040 ;
      RECT 0.280 904.960 208.720 905.520 ;
      RECT 0.280 909.440 208.720 910.000 ;
      RECT 0.280 913.920 208.720 914.480 ;
      RECT 0.280 918.400 208.720 918.960 ;
      RECT 0.280 922.880 208.720 923.440 ;
      RECT 0.280 927.360 208.720 927.920 ;
      RECT 0.280 931.840 208.720 932.400 ;
      RECT 0.280 936.320 208.720 936.880 ;
      RECT 0.280 940.800 208.720 941.360 ;
      RECT 0.280 945.280 208.720 945.840 ;
      RECT 0.280 949.760 208.720 950.320 ;
      RECT 0.280 954.240 208.720 954.800 ;
      RECT 0.280 958.720 208.720 959.280 ;
      RECT 0.280 963.200 208.720 963.760 ;
      RECT 0.280 967.680 208.720 968.240 ;
      RECT 0.280 972.160 208.720 972.720 ;
      RECT 0.280 976.640 208.720 977.200 ;
      RECT 0.280 981.120 208.720 981.680 ;
      RECT 0.280 985.600 208.720 986.160 ;
      RECT 0.280 990.080 208.720 990.640 ;
      RECT 0.280 994.560 208.720 995.120 ;
      RECT 0.280 999.040 208.720 999.600 ;
      RECT 0.280 1003.520 208.720 1004.080 ;
      RECT 0.280 1008.000 208.720 1008.560 ;
      RECT 0.280 1012.480 208.720 1013.040 ;
      RECT 0.280 1016.960 208.720 1017.520 ;
      RECT 0.280 1021.440 208.720 1022.000 ;
      RECT 0.280 1025.920 208.720 1026.480 ;
      RECT 0.280 1030.400 208.720 1030.960 ;
      RECT 0.280 1034.880 208.720 1035.440 ;
      RECT 0.280 1039.360 208.720 1039.920 ;
      RECT 0.280 1043.840 208.720 1044.400 ;
      RECT 0.280 1048.320 208.720 1048.880 ;
      RECT 0.280 1052.800 208.720 1053.360 ;
      RECT 0.280 1057.280 208.720 1057.840 ;
      RECT 0.280 1061.760 208.720 1062.320 ;
      RECT 0.280 1066.240 208.720 1066.800 ;
      RECT 0.280 1070.720 208.720 1071.280 ;
      RECT 0.280 1075.200 208.720 1075.760 ;
      RECT 0.280 1079.680 208.720 1080.240 ;
      RECT 0.280 1084.160 208.720 1084.720 ;
      RECT 0.280 1088.640 208.720 1089.200 ;
      RECT 0.280 1093.120 208.720 1093.680 ;
      RECT 0.280 1097.600 208.720 1098.160 ;
      RECT 0.280 1102.080 208.720 1102.640 ;
      RECT 0.280 1106.560 208.720 1107.120 ;
      RECT 0.280 1111.040 208.720 1111.600 ;
      RECT 0.280 1115.520 208.720 1116.080 ;
      RECT 0.280 1120.000 208.720 1120.560 ;
      RECT 0.280 1124.480 208.720 1125.040 ;
      RECT 0.280 1128.960 208.720 1129.520 ;
      RECT 0.280 1133.440 208.720 1134.000 ;
      RECT 0.280 1137.920 208.720 1138.480 ;
      RECT 0.280 1142.400 208.720 1142.960 ;
      RECT 0.280 1146.880 208.720 1147.440 ;
      RECT 0.280 1151.360 208.720 1151.920 ;
      RECT 0.280 1155.840 208.720 1156.400 ;
      RECT 0.280 1160.320 208.720 1160.880 ;
      RECT 0.280 1164.800 208.720 1165.360 ;
      RECT 0.280 1169.280 208.720 1169.840 ;
      RECT 0.280 1173.760 208.720 1174.320 ;
      RECT 0.280 1178.240 208.720 1178.800 ;
      RECT 0.280 1182.720 208.720 1183.280 ;
      RECT 0.280 1187.200 208.720 1187.760 ;
      RECT 0.280 1191.680 208.720 1192.240 ;
      RECT 0.280 1196.160 208.720 1196.720 ;
      RECT 0.280 1200.640 208.720 1201.200 ;
      RECT 0.280 1205.120 208.720 1205.680 ;
      RECT 0.280 1209.600 208.720 1210.160 ;
      RECT 0.280 1214.080 208.720 1214.640 ;
      RECT 0.280 1218.560 208.720 1219.120 ;
      RECT 0.280 1223.040 208.720 1223.600 ;
      RECT 0.280 1227.520 208.720 1228.080 ;
      RECT 0.280 1232.000 208.720 1232.560 ;
      RECT 0.280 1236.480 208.720 1237.040 ;
      RECT 0.280 1240.960 208.720 1241.520 ;
      RECT 0.280 1245.440 208.720 1246.000 ;
      RECT 0.280 1249.920 208.720 1250.480 ;
      RECT 0.280 1254.400 208.720 1254.960 ;
      RECT 0.280 1258.880 208.720 1259.440 ;
      RECT 0.280 1263.360 208.720 1263.920 ;
      RECT 0.280 1267.840 208.720 1268.400 ;
      RECT 0.280 1272.320 208.720 1272.880 ;
      RECT 0.280 1276.800 208.720 1277.360 ;
      RECT 0.280 1281.280 208.720 1281.840 ;
      RECT 0.280 1285.760 208.720 1286.320 ;
      RECT 0.280 1290.240 208.720 1290.800 ;
      RECT 0.280 1294.720 208.720 1295.280 ;
      RECT 0.280 1299.200 208.720 1299.760 ;
      RECT 0.280 1303.680 208.720 1304.240 ;
      RECT 0.280 1308.160 208.720 1308.720 ;
      RECT 0.280 1312.640 208.720 1313.200 ;
      RECT 0.280 1317.120 208.720 1317.680 ;
      RECT 0.280 1321.600 208.720 1322.160 ;
      RECT 0.280 1326.080 208.720 1326.640 ;
      RECT 0.280 1330.560 208.720 1331.120 ;
      RECT 0.280 1335.040 208.720 1335.600 ;
      RECT 0.280 1339.520 208.720 1340.080 ;
      RECT 0.280 1344.000 208.720 1344.560 ;
      RECT 0.280 1348.480 208.720 1349.040 ;
      RECT 0.280 1352.960 208.720 1353.520 ;
      RECT 0.280 1357.440 208.720 1358.000 ;
      RECT 0.280 1361.920 208.720 1362.480 ;
      RECT 0.280 1366.400 208.720 1366.960 ;
      RECT 0.280 1370.880 208.720 1371.440 ;
      RECT 0.280 1375.360 208.720 1375.920 ;
      RECT 0.280 1379.840 208.720 1380.400 ;
      RECT 0.280 1384.320 208.720 1384.880 ;
      RECT 0.280 1388.800 208.720 1389.360 ;
      RECT 0.280 1393.280 208.720 1393.840 ;
      RECT 0.280 1397.760 208.720 1398.320 ;
      RECT 0.280 1402.240 208.720 1402.800 ;
      RECT 0.280 1406.720 208.720 1407.280 ;
      RECT 0.280 1411.200 208.720 1411.760 ;
      RECT 0.280 1415.680 208.720 1416.240 ;
      RECT 0.280 1420.160 208.720 1420.720 ;
      RECT 0.280 1424.640 208.720 1425.200 ;
      RECT 0.280 1429.120 208.720 1429.680 ;
      RECT 0.280 1433.600 208.720 1434.160 ;
      RECT 0.280 1438.080 208.720 1438.640 ;
      RECT 0.280 1442.560 208.720 1443.120 ;
      RECT 0.280 1447.040 208.720 1447.600 ;
      RECT 0.280 1451.520 208.720 1452.080 ;
      RECT 0.280 1456.000 208.720 1456.560 ;
      RECT 0.280 1460.480 208.720 1461.040 ;
      RECT 0.280 1464.960 208.720 1465.520 ;
      RECT 0.280 1469.440 208.720 1470.000 ;
      RECT 0.280 1473.920 208.720 1474.480 ;
      RECT 0.280 1478.400 208.720 1478.960 ;
      RECT 0.280 1482.880 208.720 1483.440 ;
      RECT 0.280 1487.360 208.720 1487.920 ;
      RECT 0.280 1491.840 208.720 1492.400 ;
      RECT 0.280 1496.320 208.720 1496.880 ;
      RECT 0.280 1500.800 208.720 1501.360 ;
      RECT 0.280 1505.280 208.720 1505.840 ;
      RECT 0.280 1509.760 208.720 1510.320 ;
      RECT 0.280 1514.240 208.720 1514.800 ;
      RECT 0.280 1518.720 208.720 1519.280 ;
      RECT 0.280 1523.200 208.720 1523.760 ;
      RECT 0.280 1527.680 208.720 1528.240 ;
      RECT 0.280 1532.160 208.720 1532.720 ;
      RECT 0.280 1536.640 208.720 1537.200 ;
      RECT 0.280 1541.120 208.720 1541.680 ;
      RECT 0.280 1545.600 208.720 1546.160 ;
      RECT 0.280 1550.080 208.720 1550.640 ;
      RECT 0.280 1554.560 208.720 1555.120 ;
      RECT 0.280 1559.040 208.720 1559.600 ;
      RECT 0.280 1563.520 208.720 1564.080 ;
      RECT 0.280 1568.000 208.720 1568.560 ;
      RECT 0.280 1572.480 208.720 1573.040 ;
      RECT 0.280 1576.960 208.720 1577.520 ;
      RECT 0.280 1581.440 208.720 1582.000 ;
      RECT 0.280 1585.920 208.720 1586.480 ;
      RECT 0.280 1590.400 208.720 1590.960 ;
      RECT 0.280 1594.880 208.720 1595.440 ;
      RECT 0.280 1599.360 208.720 1599.920 ;
      RECT 0.280 1603.840 208.720 1604.400 ;
      RECT 0.280 1608.320 208.720 1608.880 ;
      RECT 0.280 1612.800 208.720 1613.360 ;
      RECT 0.280 1617.280 208.720 1617.840 ;
      RECT 0.280 1621.760 208.720 1622.320 ;
      RECT 0.280 1626.240 208.720 1626.800 ;
      RECT 0.280 1630.720 208.720 1631.280 ;
      RECT 0.280 1635.200 208.720 1635.760 ;
      RECT 0.280 1639.680 208.720 1640.240 ;
      RECT 0.280 1644.160 208.720 1644.720 ;
      RECT 0.280 1648.640 208.720 1649.200 ;
      RECT 0.280 1653.120 208.720 1653.680 ;
      RECT 0.280 1657.600 208.720 1658.160 ;
      RECT 0.280 1662.080 208.720 1662.640 ;
      RECT 0.280 1666.560 208.720 1667.120 ;
      RECT 0.280 1671.040 208.720 1671.600 ;
      RECT 0.280 1675.520 208.720 1676.080 ;
      RECT 0.280 1680.000 208.720 1680.560 ;
      RECT 0.280 1684.480 208.720 1685.040 ;
      RECT 0.280 1688.960 208.720 1689.520 ;
      RECT 0.280 1693.440 208.720 1694.000 ;
      RECT 0.280 1697.920 208.720 1698.480 ;
      RECT 0.280 1702.400 208.720 1702.960 ;
      RECT 0.280 1706.880 208.720 1707.440 ;
      RECT 0.280 1711.360 208.720 1711.920 ;
      RECT 0.280 1715.840 208.720 1716.400 ;
      RECT 0.280 1720.320 208.720 1720.880 ;
      RECT 0.280 1724.800 208.720 1725.360 ;
      RECT 0.280 1729.280 208.720 1729.840 ;
      RECT 0.280 1733.760 208.720 1734.320 ;
      RECT 0.280 1738.240 208.720 1738.800 ;
      RECT 0.280 1742.720 208.720 1743.280 ;
      RECT 0.280 1747.200 208.720 1747.760 ;
      RECT 0.280 1751.680 208.720 1752.240 ;
      RECT 0.280 1756.160 208.720 1756.720 ;
      RECT 0.280 1760.640 208.720 1761.200 ;
      RECT 0.280 1765.120 208.720 1765.680 ;
      RECT 0.280 1769.600 208.720 1770.160 ;
      RECT 0.280 1774.080 208.720 1774.640 ;
      RECT 0.280 1778.560 208.720 1779.120 ;
      RECT 0.280 1783.040 208.720 1783.600 ;
      RECT 0.280 1787.520 208.720 1788.080 ;
      RECT 0.280 1792.000 208.720 1792.560 ;
      RECT 0.280 1796.480 208.720 1797.040 ;
      RECT 0.280 1800.960 208.720 1801.520 ;
      RECT 0.280 1805.440 208.720 1806.000 ;
      RECT 0.280 1809.920 208.720 1810.480 ;
      RECT 0.280 1814.400 208.720 1814.960 ;
      RECT 0.280 1818.880 208.720 1819.440 ;
      RECT 0.280 1823.360 208.720 1823.920 ;
      RECT 0.280 1827.840 208.720 1828.400 ;
      RECT 0.280 1832.320 208.720 1832.880 ;
      RECT 0.280 1836.800 208.720 1837.360 ;
      RECT 0.280 1841.280 208.720 1841.840 ;
      RECT 0.280 1845.760 208.720 1846.320 ;
      RECT 0.280 1850.240 208.720 1850.800 ;
      RECT 0.280 1854.720 208.720 1855.280 ;
      RECT 0.280 1859.200 208.720 1859.760 ;
      RECT 0.280 1863.680 208.720 1864.240 ;
      RECT 0.280 1868.160 208.720 1868.720 ;
      RECT 0.280 1872.640 208.720 1873.200 ;
      RECT 0.280 1877.120 208.720 1877.680 ;
      RECT 0.280 1881.600 208.720 1882.160 ;
      RECT 0.280 1886.080 208.720 1886.640 ;
      RECT 0.280 1890.560 208.720 1891.120 ;
      RECT 0.280 1895.040 208.720 1895.600 ;
      RECT 0.280 1899.520 208.720 1900.080 ;
      RECT 0.280 1904.000 208.720 1904.560 ;
      RECT 0.280 1908.480 208.720 1909.040 ;
      RECT 0.280 1912.960 208.720 1913.520 ;
      RECT 0.280 1917.440 208.720 1918.000 ;
      RECT 0.280 1921.920 208.720 1922.480 ;
      RECT 0.280 1926.400 208.720 1926.960 ;
      RECT 0.280 1930.880 208.720 1931.440 ;
      RECT 0.280 1935.360 208.720 1935.920 ;
      RECT 0.280 1939.840 208.720 1940.400 ;
      RECT 0.280 1944.320 208.720 1944.880 ;
      RECT 0.280 1948.800 208.720 1949.360 ;
      RECT 0.280 1953.280 208.720 1953.840 ;
      RECT 0.280 1957.760 208.720 1958.320 ;
      RECT 0.280 1962.240 208.720 1962.800 ;
      RECT 0.280 1966.720 208.720 1967.280 ;
      RECT 0.280 1971.200 208.720 1971.760 ;
      RECT 0.280 1975.680 208.720 1976.240 ;
      RECT 0.280 1980.160 208.720 1980.720 ;
      RECT 0.280 1984.640 208.720 1985.200 ;
      RECT 0.280 1989.120 208.720 1989.680 ;
      RECT 0.280 1993.600 208.720 1994.160 ;
      RECT 0.280 1998.080 208.720 1998.640 ;
      RECT 0.280 2002.560 208.720 2003.120 ;
      RECT 0.280 2007.040 208.720 2007.600 ;
      RECT 0.280 2011.520 208.720 2012.080 ;
      RECT 0.280 2016.000 208.720 2016.560 ;
      RECT 0.280 2020.480 208.720 2021.040 ;
      RECT 0.280 2024.960 208.720 2025.520 ;
      RECT 0.280 2029.440 208.720 2030.000 ;
      RECT 0.280 2033.920 208.720 2034.480 ;
      RECT 0.280 2038.400 208.720 2038.960 ;
      RECT 0.280 2042.880 208.720 2043.440 ;
      RECT 0.280 2047.360 208.720 2047.920 ;
      RECT 0.280 2051.840 208.720 2052.400 ;
      RECT 0.280 2056.320 208.720 2056.880 ;
      RECT 0.280 2060.800 208.720 2061.360 ;
      RECT 0.280 2065.280 208.720 2065.840 ;
      RECT 0.280 2069.760 208.720 2070.320 ;
      RECT 0.280 2074.240 208.720 2074.800 ;
      RECT 0.280 2078.720 208.720 2079.280 ;
      RECT 0.280 2083.200 208.720 2083.760 ;
      RECT 0.280 2087.680 208.720 2088.240 ;
      RECT 0.280 2092.160 208.720 2092.720 ;
      RECT 0.280 2096.640 208.720 2097.200 ;
      RECT 0.280 2101.120 208.720 2101.680 ;
      RECT 0.280 2105.600 208.720 2106.160 ;
      RECT 0.280 2110.080 208.720 2110.640 ;
      RECT 0.280 2114.560 208.720 2115.120 ;
      RECT 0.280 2119.040 208.720 2119.600 ;
      RECT 0.280 2123.520 208.720 2124.080 ;
      RECT 0.280 2128.000 208.720 2128.560 ;
      RECT 0.280 2132.480 208.720 2133.040 ;
      RECT 0.280 2136.960 208.720 2137.520 ;
      RECT 0.280 2141.440 208.720 2142.000 ;
      RECT 0.280 2145.920 208.720 2146.480 ;
      RECT 0.280 2150.400 208.720 2150.960 ;
      RECT 0.280 2154.880 208.720 2155.440 ;
      RECT 0.280 2159.360 208.720 2159.920 ;
      RECT 0.280 2163.840 208.720 2164.400 ;
      RECT 0.280 2168.320 208.720 2168.880 ;
      RECT 0.280 2172.800 208.720 2173.360 ;
      RECT 0.280 2177.280 208.720 2177.840 ;
      RECT 0.280 2181.760 208.720 2182.320 ;
      RECT 0.280 2186.240 208.720 2186.800 ;
      RECT 0.280 2190.720 208.720 2191.280 ;
      RECT 0.280 2195.200 208.720 2195.760 ;
      RECT 0.280 2199.680 208.720 2200.240 ;
      RECT 0.280 2204.160 208.720 2204.720 ;
      RECT 0.280 2208.640 208.720 2209.200 ;
      RECT 0.280 2213.120 208.720 2213.680 ;
      RECT 0.280 2217.600 208.720 2218.160 ;
      RECT 0.280 2222.080 208.720 2222.640 ;
      RECT 0.280 2226.560 208.720 2227.120 ;
      RECT 0.280 2231.040 208.720 2231.600 ;
      RECT 0.280 2235.520 208.720 2236.080 ;
      RECT 0.280 2240.000 208.720 2240.560 ;
      RECT 0.280 2244.480 208.720 2245.040 ;
      RECT 0.280 2248.960 208.720 2249.520 ;
      RECT 0.280 2253.440 208.720 2254.000 ;
      RECT 0.280 2257.920 208.720 2258.480 ;
      RECT 0.280 2262.400 208.720 2262.960 ;
      RECT 0.280 2266.880 208.720 2267.440 ;
      RECT 0.280 2271.360 208.720 2271.920 ;
      RECT 0.280 2275.840 208.720 2276.400 ;
      RECT 0.280 2280.320 208.720 2280.880 ;
      RECT 0.280 2284.800 208.720 2285.360 ;
      RECT 0.280 2289.280 208.720 2289.840 ;
      RECT 0.280 2293.760 208.720 2294.320 ;
      RECT 0.280 2298.240 208.720 2298.800 ;
      RECT 0.280 2302.720 208.720 2303.280 ;
      RECT 0.280 2307.200 208.720 2307.760 ;
      RECT 0.280 2311.680 208.720 2312.240 ;
      RECT 0.280 2316.160 208.720 2316.720 ;
      RECT 0.280 2320.640 208.720 2321.200 ;
      RECT 0.280 2325.120 208.720 2325.680 ;
      RECT 0.280 2329.600 208.720 2330.160 ;
      RECT 0.280 2334.080 208.720 2334.640 ;
      RECT 0.280 2338.560 208.720 2339.120 ;
      RECT 0.280 2343.040 208.720 2343.600 ;
      RECT 0.280 2347.520 208.720 2348.080 ;
      RECT 0.280 2352.000 208.720 2352.560 ;
      RECT 0.280 2356.480 208.720 2357.040 ;
      RECT 0.280 2360.960 208.720 2361.520 ;
      RECT 0.280 2365.440 208.720 2366.000 ;
      RECT 0.280 2369.920 208.720 2370.480 ;
      RECT 0.280 2374.400 208.720 2374.960 ;
      RECT 0.280 2378.880 208.720 2379.440 ;
      RECT 0.280 2383.360 208.720 2383.920 ;
      RECT 0.280 2387.840 208.720 2388.400 ;
      RECT 0.280 2392.320 208.720 2392.880 ;
      RECT 0.280 2396.800 208.720 2397.360 ;
      RECT 0.280 2401.280 208.720 2401.840 ;
      RECT 0.280 2405.760 208.720 2406.320 ;
      RECT 0.280 2410.240 208.720 2410.800 ;
      RECT 0.280 2414.720 208.720 2415.280 ;
      RECT 0.280 2419.200 208.720 2419.760 ;
      RECT 0.280 2423.680 208.720 2424.240 ;
      RECT 0.280 2428.160 208.720 2428.720 ;
      RECT 0.280 2432.640 208.720 2433.200 ;
      RECT 0.280 2437.120 208.720 2437.680 ;
      RECT 0.280 2441.600 208.720 2442.160 ;
      RECT 0.280 2446.080 208.720 2446.640 ;
      RECT 0.280 2450.560 208.720 2451.120 ;
      RECT 0.280 2455.040 208.720 2455.600 ;
    END
  END VSS
  PIN VDD
    DIRECTION INOUT ;
    USE POWER ;
    PORT
      LAYER metal4 ;
      RECT 0.280 2.240 208.720 2.800 ;
      RECT 0.280 6.720 208.720 7.280 ;
      RECT 0.280 11.200 208.720 11.760 ;
      RECT 0.280 15.680 208.720 16.240 ;
      RECT 0.280 20.160 208.720 20.720 ;
      RECT 0.280 24.640 208.720 25.200 ;
      RECT 0.280 29.120 208.720 29.680 ;
      RECT 0.280 33.600 208.720 34.160 ;
      RECT 0.280 38.080 208.720 38.640 ;
      RECT 0.280 42.560 208.720 43.120 ;
      RECT 0.280 47.040 208.720 47.600 ;
      RECT 0.280 51.520 208.720 52.080 ;
      RECT 0.280 56.000 208.720 56.560 ;
      RECT 0.280 60.480 208.720 61.040 ;
      RECT 0.280 64.960 208.720 65.520 ;
      RECT 0.280 69.440 208.720 70.000 ;
      RECT 0.280 73.920 208.720 74.480 ;
      RECT 0.280 78.400 208.720 78.960 ;
      RECT 0.280 82.880 208.720 83.440 ;
      RECT 0.280 87.360 208.720 87.920 ;
      RECT 0.280 91.840 208.720 92.400 ;
      RECT 0.280 96.320 208.720 96.880 ;
      RECT 0.280 100.800 208.720 101.360 ;
      RECT 0.280 105.280 208.720 105.840 ;
      RECT 0.280 109.760 208.720 110.320 ;
      RECT 0.280 114.240 208.720 114.800 ;
      RECT 0.280 118.720 208.720 119.280 ;
      RECT 0.280 123.200 208.720 123.760 ;
      RECT 0.280 127.680 208.720 128.240 ;
      RECT 0.280 132.160 208.720 132.720 ;
      RECT 0.280 136.640 208.720 137.200 ;
      RECT 0.280 141.120 208.720 141.680 ;
      RECT 0.280 145.600 208.720 146.160 ;
      RECT 0.280 150.080 208.720 150.640 ;
      RECT 0.280 154.560 208.720 155.120 ;
      RECT 0.280 159.040 208.720 159.600 ;
      RECT 0.280 163.520 208.720 164.080 ;
      RECT 0.280 168.000 208.720 168.560 ;
      RECT 0.280 172.480 208.720 173.040 ;
      RECT 0.280 176.960 208.720 177.520 ;
      RECT 0.280 181.440 208.720 182.000 ;
      RECT 0.280 185.920 208.720 186.480 ;
      RECT 0.280 190.400 208.720 190.960 ;
      RECT 0.280 194.880 208.720 195.440 ;
      RECT 0.280 199.360 208.720 199.920 ;
      RECT 0.280 203.840 208.720 204.400 ;
      RECT 0.280 208.320 208.720 208.880 ;
      RECT 0.280 212.800 208.720 213.360 ;
      RECT 0.280 217.280 208.720 217.840 ;
      RECT 0.280 221.760 208.720 222.320 ;
      RECT 0.280 226.240 208.720 226.800 ;
      RECT 0.280 230.720 208.720 231.280 ;
      RECT 0.280 235.200 208.720 235.760 ;
      RECT 0.280 239.680 208.720 240.240 ;
      RECT 0.280 244.160 208.720 244.720 ;
      RECT 0.280 248.640 208.720 249.200 ;
      RECT 0.280 253.120 208.720 253.680 ;
      RECT 0.280 257.600 208.720 258.160 ;
      RECT 0.280 262.080 208.720 262.640 ;
      RECT 0.280 266.560 208.720 267.120 ;
      RECT 0.280 271.040 208.720 271.600 ;
      RECT 0.280 275.520 208.720 276.080 ;
      RECT 0.280 280.000 208.720 280.560 ;
      RECT 0.280 284.480 208.720 285.040 ;
      RECT 0.280 288.960 208.720 289.520 ;
      RECT 0.280 293.440 208.720 294.000 ;
      RECT 0.280 297.920 208.720 298.480 ;
      RECT 0.280 302.400 208.720 302.960 ;
      RECT 0.280 306.880 208.720 307.440 ;
      RECT 0.280 311.360 208.720 311.920 ;
      RECT 0.280 315.840 208.720 316.400 ;
      RECT 0.280 320.320 208.720 320.880 ;
      RECT 0.280 324.800 208.720 325.360 ;
      RECT 0.280 329.280 208.720 329.840 ;
      RECT 0.280 333.760 208.720 334.320 ;
      RECT 0.280 338.240 208.720 338.800 ;
      RECT 0.280 342.720 208.720 343.280 ;
      RECT 0.280 347.200 208.720 347.760 ;
      RECT 0.280 351.680 208.720 352.240 ;
      RECT 0.280 356.160 208.720 356.720 ;
      RECT 0.280 360.640 208.720 361.200 ;
      RECT 0.280 365.120 208.720 365.680 ;
      RECT 0.280 369.600 208.720 370.160 ;
      RECT 0.280 374.080 208.720 374.640 ;
      RECT 0.280 378.560 208.720 379.120 ;
      RECT 0.280 383.040 208.720 383.600 ;
      RECT 0.280 387.520 208.720 388.080 ;
      RECT 0.280 392.000 208.720 392.560 ;
      RECT 0.280 396.480 208.720 397.040 ;
      RECT 0.280 400.960 208.720 401.520 ;
      RECT 0.280 405.440 208.720 406.000 ;
      RECT 0.280 409.920 208.720 410.480 ;
      RECT 0.280 414.400 208.720 414.960 ;
      RECT 0.280 418.880 208.720 419.440 ;
      RECT 0.280 423.360 208.720 423.920 ;
      RECT 0.280 427.840 208.720 428.400 ;
      RECT 0.280 432.320 208.720 432.880 ;
      RECT 0.280 436.800 208.720 437.360 ;
      RECT 0.280 441.280 208.720 441.840 ;
      RECT 0.280 445.760 208.720 446.320 ;
      RECT 0.280 450.240 208.720 450.800 ;
      RECT 0.280 454.720 208.720 455.280 ;
      RECT 0.280 459.200 208.720 459.760 ;
      RECT 0.280 463.680 208.720 464.240 ;
      RECT 0.280 468.160 208.720 468.720 ;
      RECT 0.280 472.640 208.720 473.200 ;
      RECT 0.280 477.120 208.720 477.680 ;
      RECT 0.280 481.600 208.720 482.160 ;
      RECT 0.280 486.080 208.720 486.640 ;
      RECT 0.280 490.560 208.720 491.120 ;
      RECT 0.280 495.040 208.720 495.600 ;
      RECT 0.280 499.520 208.720 500.080 ;
      RECT 0.280 504.000 208.720 504.560 ;
      RECT 0.280 508.480 208.720 509.040 ;
      RECT 0.280 512.960 208.720 513.520 ;
      RECT 0.280 517.440 208.720 518.000 ;
      RECT 0.280 521.920 208.720 522.480 ;
      RECT 0.280 526.400 208.720 526.960 ;
      RECT 0.280 530.880 208.720 531.440 ;
      RECT 0.280 535.360 208.720 535.920 ;
      RECT 0.280 539.840 208.720 540.400 ;
      RECT 0.280 544.320 208.720 544.880 ;
      RECT 0.280 548.800 208.720 549.360 ;
      RECT 0.280 553.280 208.720 553.840 ;
      RECT 0.280 557.760 208.720 558.320 ;
      RECT 0.280 562.240 208.720 562.800 ;
      RECT 0.280 566.720 208.720 567.280 ;
      RECT 0.280 571.200 208.720 571.760 ;
      RECT 0.280 575.680 208.720 576.240 ;
      RECT 0.280 580.160 208.720 580.720 ;
      RECT 0.280 584.640 208.720 585.200 ;
      RECT 0.280 589.120 208.720 589.680 ;
      RECT 0.280 593.600 208.720 594.160 ;
      RECT 0.280 598.080 208.720 598.640 ;
      RECT 0.280 602.560 208.720 603.120 ;
      RECT 0.280 607.040 208.720 607.600 ;
      RECT 0.280 611.520 208.720 612.080 ;
      RECT 0.280 616.000 208.720 616.560 ;
      RECT 0.280 620.480 208.720 621.040 ;
      RECT 0.280 624.960 208.720 625.520 ;
      RECT 0.280 629.440 208.720 630.000 ;
      RECT 0.280 633.920 208.720 634.480 ;
      RECT 0.280 638.400 208.720 638.960 ;
      RECT 0.280 642.880 208.720 643.440 ;
      RECT 0.280 647.360 208.720 647.920 ;
      RECT 0.280 651.840 208.720 652.400 ;
      RECT 0.280 656.320 208.720 656.880 ;
      RECT 0.280 660.800 208.720 661.360 ;
      RECT 0.280 665.280 208.720 665.840 ;
      RECT 0.280 669.760 208.720 670.320 ;
      RECT 0.280 674.240 208.720 674.800 ;
      RECT 0.280 678.720 208.720 679.280 ;
      RECT 0.280 683.200 208.720 683.760 ;
      RECT 0.280 687.680 208.720 688.240 ;
      RECT 0.280 692.160 208.720 692.720 ;
      RECT 0.280 696.640 208.720 697.200 ;
      RECT 0.280 701.120 208.720 701.680 ;
      RECT 0.280 705.600 208.720 706.160 ;
      RECT 0.280 710.080 208.720 710.640 ;
      RECT 0.280 714.560 208.720 715.120 ;
      RECT 0.280 719.040 208.720 719.600 ;
      RECT 0.280 723.520 208.720 724.080 ;
      RECT 0.280 728.000 208.720 728.560 ;
      RECT 0.280 732.480 208.720 733.040 ;
      RECT 0.280 736.960 208.720 737.520 ;
      RECT 0.280 741.440 208.720 742.000 ;
      RECT 0.280 745.920 208.720 746.480 ;
      RECT 0.280 750.400 208.720 750.960 ;
      RECT 0.280 754.880 208.720 755.440 ;
      RECT 0.280 759.360 208.720 759.920 ;
      RECT 0.280 763.840 208.720 764.400 ;
      RECT 0.280 768.320 208.720 768.880 ;
      RECT 0.280 772.800 208.720 773.360 ;
      RECT 0.280 777.280 208.720 777.840 ;
      RECT 0.280 781.760 208.720 782.320 ;
      RECT 0.280 786.240 208.720 786.800 ;
      RECT 0.280 790.720 208.720 791.280 ;
      RECT 0.280 795.200 208.720 795.760 ;
      RECT 0.280 799.680 208.720 800.240 ;
      RECT 0.280 804.160 208.720 804.720 ;
      RECT 0.280 808.640 208.720 809.200 ;
      RECT 0.280 813.120 208.720 813.680 ;
      RECT 0.280 817.600 208.720 818.160 ;
      RECT 0.280 822.080 208.720 822.640 ;
      RECT 0.280 826.560 208.720 827.120 ;
      RECT 0.280 831.040 208.720 831.600 ;
      RECT 0.280 835.520 208.720 836.080 ;
      RECT 0.280 840.000 208.720 840.560 ;
      RECT 0.280 844.480 208.720 845.040 ;
      RECT 0.280 848.960 208.720 849.520 ;
      RECT 0.280 853.440 208.720 854.000 ;
      RECT 0.280 857.920 208.720 858.480 ;
      RECT 0.280 862.400 208.720 862.960 ;
      RECT 0.280 866.880 208.720 867.440 ;
      RECT 0.280 871.360 208.720 871.920 ;
      RECT 0.280 875.840 208.720 876.400 ;
      RECT 0.280 880.320 208.720 880.880 ;
      RECT 0.280 884.800 208.720 885.360 ;
      RECT 0.280 889.280 208.720 889.840 ;
      RECT 0.280 893.760 208.720 894.320 ;
      RECT 0.280 898.240 208.720 898.800 ;
      RECT 0.280 902.720 208.720 903.280 ;
      RECT 0.280 907.200 208.720 907.760 ;
      RECT 0.280 911.680 208.720 912.240 ;
      RECT 0.280 916.160 208.720 916.720 ;
      RECT 0.280 920.640 208.720 921.200 ;
      RECT 0.280 925.120 208.720 925.680 ;
      RECT 0.280 929.600 208.720 930.160 ;
      RECT 0.280 934.080 208.720 934.640 ;
      RECT 0.280 938.560 208.720 939.120 ;
      RECT 0.280 943.040 208.720 943.600 ;
      RECT 0.280 947.520 208.720 948.080 ;
      RECT 0.280 952.000 208.720 952.560 ;
      RECT 0.280 956.480 208.720 957.040 ;
      RECT 0.280 960.960 208.720 961.520 ;
      RECT 0.280 965.440 208.720 966.000 ;
      RECT 0.280 969.920 208.720 970.480 ;
      RECT 0.280 974.400 208.720 974.960 ;
      RECT 0.280 978.880 208.720 979.440 ;
      RECT 0.280 983.360 208.720 983.920 ;
      RECT 0.280 987.840 208.720 988.400 ;
      RECT 0.280 992.320 208.720 992.880 ;
      RECT 0.280 996.800 208.720 997.360 ;
      RECT 0.280 1001.280 208.720 1001.840 ;
      RECT 0.280 1005.760 208.720 1006.320 ;
      RECT 0.280 1010.240 208.720 1010.800 ;
      RECT 0.280 1014.720 208.720 1015.280 ;
      RECT 0.280 1019.200 208.720 1019.760 ;
      RECT 0.280 1023.680 208.720 1024.240 ;
      RECT 0.280 1028.160 208.720 1028.720 ;
      RECT 0.280 1032.640 208.720 1033.200 ;
      RECT 0.280 1037.120 208.720 1037.680 ;
      RECT 0.280 1041.600 208.720 1042.160 ;
      RECT 0.280 1046.080 208.720 1046.640 ;
      RECT 0.280 1050.560 208.720 1051.120 ;
      RECT 0.280 1055.040 208.720 1055.600 ;
      RECT 0.280 1059.520 208.720 1060.080 ;
      RECT 0.280 1064.000 208.720 1064.560 ;
      RECT 0.280 1068.480 208.720 1069.040 ;
      RECT 0.280 1072.960 208.720 1073.520 ;
      RECT 0.280 1077.440 208.720 1078.000 ;
      RECT 0.280 1081.920 208.720 1082.480 ;
      RECT 0.280 1086.400 208.720 1086.960 ;
      RECT 0.280 1090.880 208.720 1091.440 ;
      RECT 0.280 1095.360 208.720 1095.920 ;
      RECT 0.280 1099.840 208.720 1100.400 ;
      RECT 0.280 1104.320 208.720 1104.880 ;
      RECT 0.280 1108.800 208.720 1109.360 ;
      RECT 0.280 1113.280 208.720 1113.840 ;
      RECT 0.280 1117.760 208.720 1118.320 ;
      RECT 0.280 1122.240 208.720 1122.800 ;
      RECT 0.280 1126.720 208.720 1127.280 ;
      RECT 0.280 1131.200 208.720 1131.760 ;
      RECT 0.280 1135.680 208.720 1136.240 ;
      RECT 0.280 1140.160 208.720 1140.720 ;
      RECT 0.280 1144.640 208.720 1145.200 ;
      RECT 0.280 1149.120 208.720 1149.680 ;
      RECT 0.280 1153.600 208.720 1154.160 ;
      RECT 0.280 1158.080 208.720 1158.640 ;
      RECT 0.280 1162.560 208.720 1163.120 ;
      RECT 0.280 1167.040 208.720 1167.600 ;
      RECT 0.280 1171.520 208.720 1172.080 ;
      RECT 0.280 1176.000 208.720 1176.560 ;
      RECT 0.280 1180.480 208.720 1181.040 ;
      RECT 0.280 1184.960 208.720 1185.520 ;
      RECT 0.280 1189.440 208.720 1190.000 ;
      RECT 0.280 1193.920 208.720 1194.480 ;
      RECT 0.280 1198.400 208.720 1198.960 ;
      RECT 0.280 1202.880 208.720 1203.440 ;
      RECT 0.280 1207.360 208.720 1207.920 ;
      RECT 0.280 1211.840 208.720 1212.400 ;
      RECT 0.280 1216.320 208.720 1216.880 ;
      RECT 0.280 1220.800 208.720 1221.360 ;
      RECT 0.280 1225.280 208.720 1225.840 ;
      RECT 0.280 1229.760 208.720 1230.320 ;
      RECT 0.280 1234.240 208.720 1234.800 ;
      RECT 0.280 1238.720 208.720 1239.280 ;
      RECT 0.280 1243.200 208.720 1243.760 ;
      RECT 0.280 1247.680 208.720 1248.240 ;
      RECT 0.280 1252.160 208.720 1252.720 ;
      RECT 0.280 1256.640 208.720 1257.200 ;
      RECT 0.280 1261.120 208.720 1261.680 ;
      RECT 0.280 1265.600 208.720 1266.160 ;
      RECT 0.280 1270.080 208.720 1270.640 ;
      RECT 0.280 1274.560 208.720 1275.120 ;
      RECT 0.280 1279.040 208.720 1279.600 ;
      RECT 0.280 1283.520 208.720 1284.080 ;
      RECT 0.280 1288.000 208.720 1288.560 ;
      RECT 0.280 1292.480 208.720 1293.040 ;
      RECT 0.280 1296.960 208.720 1297.520 ;
      RECT 0.280 1301.440 208.720 1302.000 ;
      RECT 0.280 1305.920 208.720 1306.480 ;
      RECT 0.280 1310.400 208.720 1310.960 ;
      RECT 0.280 1314.880 208.720 1315.440 ;
      RECT 0.280 1319.360 208.720 1319.920 ;
      RECT 0.280 1323.840 208.720 1324.400 ;
      RECT 0.280 1328.320 208.720 1328.880 ;
      RECT 0.280 1332.800 208.720 1333.360 ;
      RECT 0.280 1337.280 208.720 1337.840 ;
      RECT 0.280 1341.760 208.720 1342.320 ;
      RECT 0.280 1346.240 208.720 1346.800 ;
      RECT 0.280 1350.720 208.720 1351.280 ;
      RECT 0.280 1355.200 208.720 1355.760 ;
      RECT 0.280 1359.680 208.720 1360.240 ;
      RECT 0.280 1364.160 208.720 1364.720 ;
      RECT 0.280 1368.640 208.720 1369.200 ;
      RECT 0.280 1373.120 208.720 1373.680 ;
      RECT 0.280 1377.600 208.720 1378.160 ;
      RECT 0.280 1382.080 208.720 1382.640 ;
      RECT 0.280 1386.560 208.720 1387.120 ;
      RECT 0.280 1391.040 208.720 1391.600 ;
      RECT 0.280 1395.520 208.720 1396.080 ;
      RECT 0.280 1400.000 208.720 1400.560 ;
      RECT 0.280 1404.480 208.720 1405.040 ;
      RECT 0.280 1408.960 208.720 1409.520 ;
      RECT 0.280 1413.440 208.720 1414.000 ;
      RECT 0.280 1417.920 208.720 1418.480 ;
      RECT 0.280 1422.400 208.720 1422.960 ;
      RECT 0.280 1426.880 208.720 1427.440 ;
      RECT 0.280 1431.360 208.720 1431.920 ;
      RECT 0.280 1435.840 208.720 1436.400 ;
      RECT 0.280 1440.320 208.720 1440.880 ;
      RECT 0.280 1444.800 208.720 1445.360 ;
      RECT 0.280 1449.280 208.720 1449.840 ;
      RECT 0.280 1453.760 208.720 1454.320 ;
      RECT 0.280 1458.240 208.720 1458.800 ;
      RECT 0.280 1462.720 208.720 1463.280 ;
      RECT 0.280 1467.200 208.720 1467.760 ;
      RECT 0.280 1471.680 208.720 1472.240 ;
      RECT 0.280 1476.160 208.720 1476.720 ;
      RECT 0.280 1480.640 208.720 1481.200 ;
      RECT 0.280 1485.120 208.720 1485.680 ;
      RECT 0.280 1489.600 208.720 1490.160 ;
      RECT 0.280 1494.080 208.720 1494.640 ;
      RECT 0.280 1498.560 208.720 1499.120 ;
      RECT 0.280 1503.040 208.720 1503.600 ;
      RECT 0.280 1507.520 208.720 1508.080 ;
      RECT 0.280 1512.000 208.720 1512.560 ;
      RECT 0.280 1516.480 208.720 1517.040 ;
      RECT 0.280 1520.960 208.720 1521.520 ;
      RECT 0.280 1525.440 208.720 1526.000 ;
      RECT 0.280 1529.920 208.720 1530.480 ;
      RECT 0.280 1534.400 208.720 1534.960 ;
      RECT 0.280 1538.880 208.720 1539.440 ;
      RECT 0.280 1543.360 208.720 1543.920 ;
      RECT 0.280 1547.840 208.720 1548.400 ;
      RECT 0.280 1552.320 208.720 1552.880 ;
      RECT 0.280 1556.800 208.720 1557.360 ;
      RECT 0.280 1561.280 208.720 1561.840 ;
      RECT 0.280 1565.760 208.720 1566.320 ;
      RECT 0.280 1570.240 208.720 1570.800 ;
      RECT 0.280 1574.720 208.720 1575.280 ;
      RECT 0.280 1579.200 208.720 1579.760 ;
      RECT 0.280 1583.680 208.720 1584.240 ;
      RECT 0.280 1588.160 208.720 1588.720 ;
      RECT 0.280 1592.640 208.720 1593.200 ;
      RECT 0.280 1597.120 208.720 1597.680 ;
      RECT 0.280 1601.600 208.720 1602.160 ;
      RECT 0.280 1606.080 208.720 1606.640 ;
      RECT 0.280 1610.560 208.720 1611.120 ;
      RECT 0.280 1615.040 208.720 1615.600 ;
      RECT 0.280 1619.520 208.720 1620.080 ;
      RECT 0.280 1624.000 208.720 1624.560 ;
      RECT 0.280 1628.480 208.720 1629.040 ;
      RECT 0.280 1632.960 208.720 1633.520 ;
      RECT 0.280 1637.440 208.720 1638.000 ;
      RECT 0.280 1641.920 208.720 1642.480 ;
      RECT 0.280 1646.400 208.720 1646.960 ;
      RECT 0.280 1650.880 208.720 1651.440 ;
      RECT 0.280 1655.360 208.720 1655.920 ;
      RECT 0.280 1659.840 208.720 1660.400 ;
      RECT 0.280 1664.320 208.720 1664.880 ;
      RECT 0.280 1668.800 208.720 1669.360 ;
      RECT 0.280 1673.280 208.720 1673.840 ;
      RECT 0.280 1677.760 208.720 1678.320 ;
      RECT 0.280 1682.240 208.720 1682.800 ;
      RECT 0.280 1686.720 208.720 1687.280 ;
      RECT 0.280 1691.200 208.720 1691.760 ;
      RECT 0.280 1695.680 208.720 1696.240 ;
      RECT 0.280 1700.160 208.720 1700.720 ;
      RECT 0.280 1704.640 208.720 1705.200 ;
      RECT 0.280 1709.120 208.720 1709.680 ;
      RECT 0.280 1713.600 208.720 1714.160 ;
      RECT 0.280 1718.080 208.720 1718.640 ;
      RECT 0.280 1722.560 208.720 1723.120 ;
      RECT 0.280 1727.040 208.720 1727.600 ;
      RECT 0.280 1731.520 208.720 1732.080 ;
      RECT 0.280 1736.000 208.720 1736.560 ;
      RECT 0.280 1740.480 208.720 1741.040 ;
      RECT 0.280 1744.960 208.720 1745.520 ;
      RECT 0.280 1749.440 208.720 1750.000 ;
      RECT 0.280 1753.920 208.720 1754.480 ;
      RECT 0.280 1758.400 208.720 1758.960 ;
      RECT 0.280 1762.880 208.720 1763.440 ;
      RECT 0.280 1767.360 208.720 1767.920 ;
      RECT 0.280 1771.840 208.720 1772.400 ;
      RECT 0.280 1776.320 208.720 1776.880 ;
      RECT 0.280 1780.800 208.720 1781.360 ;
      RECT 0.280 1785.280 208.720 1785.840 ;
      RECT 0.280 1789.760 208.720 1790.320 ;
      RECT 0.280 1794.240 208.720 1794.800 ;
      RECT 0.280 1798.720 208.720 1799.280 ;
      RECT 0.280 1803.200 208.720 1803.760 ;
      RECT 0.280 1807.680 208.720 1808.240 ;
      RECT 0.280 1812.160 208.720 1812.720 ;
      RECT 0.280 1816.640 208.720 1817.200 ;
      RECT 0.280 1821.120 208.720 1821.680 ;
      RECT 0.280 1825.600 208.720 1826.160 ;
      RECT 0.280 1830.080 208.720 1830.640 ;
      RECT 0.280 1834.560 208.720 1835.120 ;
      RECT 0.280 1839.040 208.720 1839.600 ;
      RECT 0.280 1843.520 208.720 1844.080 ;
      RECT 0.280 1848.000 208.720 1848.560 ;
      RECT 0.280 1852.480 208.720 1853.040 ;
      RECT 0.280 1856.960 208.720 1857.520 ;
      RECT 0.280 1861.440 208.720 1862.000 ;
      RECT 0.280 1865.920 208.720 1866.480 ;
      RECT 0.280 1870.400 208.720 1870.960 ;
      RECT 0.280 1874.880 208.720 1875.440 ;
      RECT 0.280 1879.360 208.720 1879.920 ;
      RECT 0.280 1883.840 208.720 1884.400 ;
      RECT 0.280 1888.320 208.720 1888.880 ;
      RECT 0.280 1892.800 208.720 1893.360 ;
      RECT 0.280 1897.280 208.720 1897.840 ;
      RECT 0.280 1901.760 208.720 1902.320 ;
      RECT 0.280 1906.240 208.720 1906.800 ;
      RECT 0.280 1910.720 208.720 1911.280 ;
      RECT 0.280 1915.200 208.720 1915.760 ;
      RECT 0.280 1919.680 208.720 1920.240 ;
      RECT 0.280 1924.160 208.720 1924.720 ;
      RECT 0.280 1928.640 208.720 1929.200 ;
      RECT 0.280 1933.120 208.720 1933.680 ;
      RECT 0.280 1937.600 208.720 1938.160 ;
      RECT 0.280 1942.080 208.720 1942.640 ;
      RECT 0.280 1946.560 208.720 1947.120 ;
      RECT 0.280 1951.040 208.720 1951.600 ;
      RECT 0.280 1955.520 208.720 1956.080 ;
      RECT 0.280 1960.000 208.720 1960.560 ;
      RECT 0.280 1964.480 208.720 1965.040 ;
      RECT 0.280 1968.960 208.720 1969.520 ;
      RECT 0.280 1973.440 208.720 1974.000 ;
      RECT 0.280 1977.920 208.720 1978.480 ;
      RECT 0.280 1982.400 208.720 1982.960 ;
      RECT 0.280 1986.880 208.720 1987.440 ;
      RECT 0.280 1991.360 208.720 1991.920 ;
      RECT 0.280 1995.840 208.720 1996.400 ;
      RECT 0.280 2000.320 208.720 2000.880 ;
      RECT 0.280 2004.800 208.720 2005.360 ;
      RECT 0.280 2009.280 208.720 2009.840 ;
      RECT 0.280 2013.760 208.720 2014.320 ;
      RECT 0.280 2018.240 208.720 2018.800 ;
      RECT 0.280 2022.720 208.720 2023.280 ;
      RECT 0.280 2027.200 208.720 2027.760 ;
      RECT 0.280 2031.680 208.720 2032.240 ;
      RECT 0.280 2036.160 208.720 2036.720 ;
      RECT 0.280 2040.640 208.720 2041.200 ;
      RECT 0.280 2045.120 208.720 2045.680 ;
      RECT 0.280 2049.600 208.720 2050.160 ;
      RECT 0.280 2054.080 208.720 2054.640 ;
      RECT 0.280 2058.560 208.720 2059.120 ;
      RECT 0.280 2063.040 208.720 2063.600 ;
      RECT 0.280 2067.520 208.720 2068.080 ;
      RECT 0.280 2072.000 208.720 2072.560 ;
      RECT 0.280 2076.480 208.720 2077.040 ;
      RECT 0.280 2080.960 208.720 2081.520 ;
      RECT 0.280 2085.440 208.720 2086.000 ;
      RECT 0.280 2089.920 208.720 2090.480 ;
      RECT 0.280 2094.400 208.720 2094.960 ;
      RECT 0.280 2098.880 208.720 2099.440 ;
      RECT 0.280 2103.360 208.720 2103.920 ;
      RECT 0.280 2107.840 208.720 2108.400 ;
      RECT 0.280 2112.320 208.720 2112.880 ;
      RECT 0.280 2116.800 208.720 2117.360 ;
      RECT 0.280 2121.280 208.720 2121.840 ;
      RECT 0.280 2125.760 208.720 2126.320 ;
      RECT 0.280 2130.240 208.720 2130.800 ;
      RECT 0.280 2134.720 208.720 2135.280 ;
      RECT 0.280 2139.200 208.720 2139.760 ;
      RECT 0.280 2143.680 208.720 2144.240 ;
      RECT 0.280 2148.160 208.720 2148.720 ;
      RECT 0.280 2152.640 208.720 2153.200 ;
      RECT 0.280 2157.120 208.720 2157.680 ;
      RECT 0.280 2161.600 208.720 2162.160 ;
      RECT 0.280 2166.080 208.720 2166.640 ;
      RECT 0.280 2170.560 208.720 2171.120 ;
      RECT 0.280 2175.040 208.720 2175.600 ;
      RECT 0.280 2179.520 208.720 2180.080 ;
      RECT 0.280 2184.000 208.720 2184.560 ;
      RECT 0.280 2188.480 208.720 2189.040 ;
      RECT 0.280 2192.960 208.720 2193.520 ;
      RECT 0.280 2197.440 208.720 2198.000 ;
      RECT 0.280 2201.920 208.720 2202.480 ;
      RECT 0.280 2206.400 208.720 2206.960 ;
      RECT 0.280 2210.880 208.720 2211.440 ;
      RECT 0.280 2215.360 208.720 2215.920 ;
      RECT 0.280 2219.840 208.720 2220.400 ;
      RECT 0.280 2224.320 208.720 2224.880 ;
      RECT 0.280 2228.800 208.720 2229.360 ;
      RECT 0.280 2233.280 208.720 2233.840 ;
      RECT 0.280 2237.760 208.720 2238.320 ;
      RECT 0.280 2242.240 208.720 2242.800 ;
      RECT 0.280 2246.720 208.720 2247.280 ;
      RECT 0.280 2251.200 208.720 2251.760 ;
      RECT 0.280 2255.680 208.720 2256.240 ;
      RECT 0.280 2260.160 208.720 2260.720 ;
      RECT 0.280 2264.640 208.720 2265.200 ;
      RECT 0.280 2269.120 208.720 2269.680 ;
      RECT 0.280 2273.600 208.720 2274.160 ;
      RECT 0.280 2278.080 208.720 2278.640 ;
      RECT 0.280 2282.560 208.720 2283.120 ;
      RECT 0.280 2287.040 208.720 2287.600 ;
      RECT 0.280 2291.520 208.720 2292.080 ;
      RECT 0.280 2296.000 208.720 2296.560 ;
      RECT 0.280 2300.480 208.720 2301.040 ;
      RECT 0.280 2304.960 208.720 2305.520 ;
      RECT 0.280 2309.440 208.720 2310.000 ;
      RECT 0.280 2313.920 208.720 2314.480 ;
      RECT 0.280 2318.400 208.720 2318.960 ;
      RECT 0.280 2322.880 208.720 2323.440 ;
      RECT 0.280 2327.360 208.720 2327.920 ;
      RECT 0.280 2331.840 208.720 2332.400 ;
      RECT 0.280 2336.320 208.720 2336.880 ;
      RECT 0.280 2340.800 208.720 2341.360 ;
      RECT 0.280 2345.280 208.720 2345.840 ;
      RECT 0.280 2349.760 208.720 2350.320 ;
      RECT 0.280 2354.240 208.720 2354.800 ;
      RECT 0.280 2358.720 208.720 2359.280 ;
      RECT 0.280 2363.200 208.720 2363.760 ;
      RECT 0.280 2367.680 208.720 2368.240 ;
      RECT 0.280 2372.160 208.720 2372.720 ;
      RECT 0.280 2376.640 208.720 2377.200 ;
      RECT 0.280 2381.120 208.720 2381.680 ;
      RECT 0.280 2385.600 208.720 2386.160 ;
      RECT 0.280 2390.080 208.720 2390.640 ;
      RECT 0.280 2394.560 208.720 2395.120 ;
      RECT 0.280 2399.040 208.720 2399.600 ;
      RECT 0.280 2403.520 208.720 2404.080 ;
      RECT 0.280 2408.000 208.720 2408.560 ;
      RECT 0.280 2412.480 208.720 2413.040 ;
      RECT 0.280 2416.960 208.720 2417.520 ;
      RECT 0.280 2421.440 208.720 2422.000 ;
      RECT 0.280 2425.920 208.720 2426.480 ;
      RECT 0.280 2430.400 208.720 2430.960 ;
      RECT 0.280 2434.880 208.720 2435.440 ;
      RECT 0.280 2439.360 208.720 2439.920 ;
      RECT 0.280 2443.840 208.720 2444.400 ;
      RECT 0.280 2448.320 208.720 2448.880 ;
      RECT 0.280 2452.800 208.720 2453.360 ;
      RECT 0.280 2457.280 208.720 2457.840 ;
    END
  END VDD
  OBS
    LAYER metal1 ;
    RECT 0 0 209.000 2458.400 ;
    LAYER metal2 ;
    RECT 0 0 209.000 2458.400 ;
    LAYER metal3 ;
    RECT 0 0 209.000 2458.400 ;
    LAYER metal4 ;
    RECT 0 0 209.000 2458.400 ;
  END
END fakeram45_16384x64

END LIBRARY
